VERSION 5.7 ;
  NOWIREEXTENSIONATPIN ON ;
  DIVIDERCHAR "/" ;
  BUSBITCHARS "[]" ;
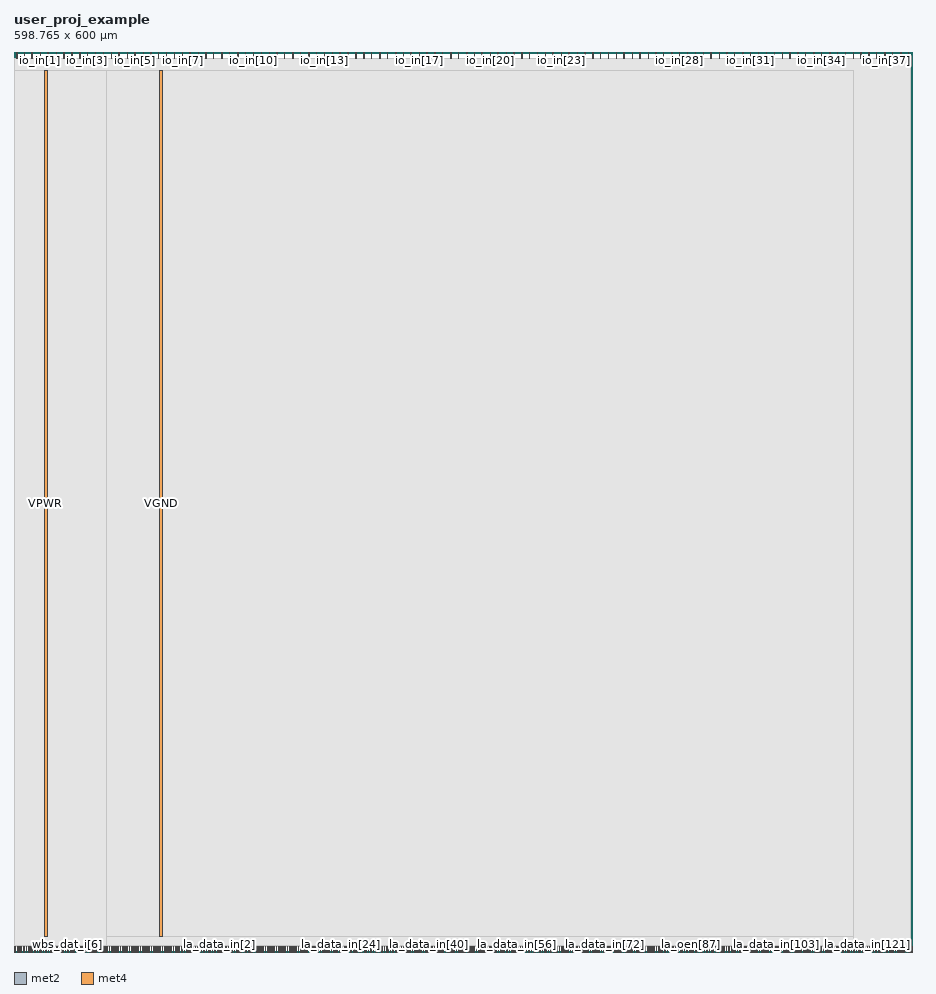
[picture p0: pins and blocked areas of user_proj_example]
MACRO user_proj_example
  CLASS BLOCK ;
  FOREIGN user_proj_example ;
  ORIGIN -0.005 0.000 ;
  SIZE 598.765 BY 600.000 ;
  PIN io_in[0]
    DIRECTION INPUT ;
    PORT
      LAYER met2 ;
        RECT 1.870 596.000 2.150 600.000 ;
    END
  END io_in[0]
  PIN io_in[10]
    DIRECTION INPUT ;
    PORT
      LAYER met2 ;
        RECT 159.650 596.000 159.930 600.000 ;
    END
  END io_in[10]
  PIN io_in[11]
    DIRECTION INPUT ;
    PORT
      LAYER met2 ;
        RECT 175.290 596.000 175.570 600.000 ;
    END
  END io_in[11]
  PIN io_in[12]
    DIRECTION INPUT ;
    PORT
      LAYER met2 ;
        RECT 190.930 596.000 191.210 600.000 ;
    END
  END io_in[12]
  PIN io_in[13]
    DIRECTION INPUT ;
    PORT
      LAYER met2 ;
        RECT 207.030 596.000 207.310 600.000 ;
    END
  END io_in[13]
  PIN io_in[14]
    DIRECTION INPUT ;
    PORT
      LAYER met2 ;
        RECT 222.670 596.000 222.950 600.000 ;
    END
  END io_in[14]
  PIN io_in[15]
    DIRECTION INPUT ;
    PORT
      LAYER met2 ;
        RECT 238.310 596.000 238.590 600.000 ;
    END
  END io_in[15]
  PIN io_in[16]
    DIRECTION INPUT ;
    PORT
      LAYER met2 ;
        RECT 254.410 596.000 254.690 600.000 ;
    END
  END io_in[16]
  PIN io_in[17]
    DIRECTION INPUT ;
    PORT
      LAYER met2 ;
        RECT 270.050 596.000 270.330 600.000 ;
    END
  END io_in[17]
  PIN io_in[18]
    DIRECTION INPUT ;
    PORT
      LAYER met2 ;
        RECT 285.690 596.000 285.970 600.000 ;
    END
  END io_in[18]
  PIN io_in[19]
    DIRECTION INPUT ;
    PORT
      LAYER met2 ;
        RECT 301.790 596.000 302.070 600.000 ;
    END
  END io_in[19]
  PIN io_in[1]
    DIRECTION INPUT ;
    PORT
      LAYER met2 ;
        RECT 17.510 596.000 17.790 600.000 ;
    END
  END io_in[1]
  PIN io_in[20]
    DIRECTION INPUT ;
    PORT
      LAYER met2 ;
        RECT 317.430 596.000 317.710 600.000 ;
    END
  END io_in[20]
  PIN io_in[21]
    DIRECTION INPUT ;
    PORT
      LAYER met2 ;
        RECT 333.070 596.000 333.350 600.000 ;
    END
  END io_in[21]
  PIN io_in[22]
    DIRECTION INPUT ;
    PORT
      LAYER met2 ;
        RECT 348.710 596.000 348.990 600.000 ;
    END
  END io_in[22]
  PIN io_in[23]
    DIRECTION INPUT ;
    PORT
      LAYER met2 ;
        RECT 364.810 596.000 365.090 600.000 ;
    END
  END io_in[23]
  PIN io_in[24]
    DIRECTION INPUT ;
    PORT
      LAYER met2 ;
        RECT 380.450 596.000 380.730 600.000 ;
    END
  END io_in[24]
  PIN io_in[25]
    DIRECTION INPUT ;
    PORT
      LAYER met2 ;
        RECT 396.090 596.000 396.370 600.000 ;
    END
  END io_in[25]
  PIN io_in[26]
    DIRECTION INPUT ;
    PORT
      LAYER met2 ;
        RECT 412.190 596.000 412.470 600.000 ;
    END
  END io_in[26]
  PIN io_in[27]
    DIRECTION INPUT ;
    PORT
      LAYER met2 ;
        RECT 427.830 596.000 428.110 600.000 ;
    END
  END io_in[27]
  PIN io_in[28]
    DIRECTION INPUT ;
    PORT
      LAYER met2 ;
        RECT 443.470 596.000 443.750 600.000 ;
    END
  END io_in[28]
  PIN io_in[29]
    DIRECTION INPUT ;
    PORT
      LAYER met2 ;
        RECT 459.570 596.000 459.850 600.000 ;
    END
  END io_in[29]
  PIN io_in[2]
    DIRECTION INPUT ;
    PORT
      LAYER met2 ;
        RECT 33.150 596.000 33.430 600.000 ;
    END
  END io_in[2]
  PIN io_in[30]
    DIRECTION INPUT ;
    PORT
      LAYER met2 ;
        RECT 475.210 596.000 475.490 600.000 ;
    END
  END io_in[30]
  PIN io_in[31]
    DIRECTION INPUT ;
    PORT
      LAYER met2 ;
        RECT 490.850 596.000 491.130 600.000 ;
    END
  END io_in[31]
  PIN io_in[32]
    DIRECTION INPUT ;
    PORT
      LAYER met2 ;
        RECT 506.950 596.000 507.230 600.000 ;
    END
  END io_in[32]
  PIN io_in[33]
    DIRECTION INPUT ;
    PORT
      LAYER met2 ;
        RECT 522.590 596.000 522.870 600.000 ;
    END
  END io_in[33]
  PIN io_in[34]
    DIRECTION INPUT ;
    PORT
      LAYER met2 ;
        RECT 538.230 596.000 538.510 600.000 ;
    END
  END io_in[34]
  PIN io_in[35]
    DIRECTION INPUT ;
    PORT
      LAYER met2 ;
        RECT 554.330 596.000 554.610 600.000 ;
    END
  END io_in[35]
  PIN io_in[36]
    DIRECTION INPUT ;
    PORT
      LAYER met2 ;
        RECT 569.970 596.000 570.250 600.000 ;
    END
  END io_in[36]
  PIN io_in[37]
    DIRECTION INPUT ;
    PORT
      LAYER met2 ;
        RECT 585.610 596.000 585.890 600.000 ;
    END
  END io_in[37]
  PIN io_in[3]
    DIRECTION INPUT ;
    PORT
      LAYER met2 ;
        RECT 48.790 596.000 49.070 600.000 ;
    END
  END io_in[3]
  PIN io_in[4]
    DIRECTION INPUT ;
    PORT
      LAYER met2 ;
        RECT 64.890 596.000 65.170 600.000 ;
    END
  END io_in[4]
  PIN io_in[5]
    DIRECTION INPUT ;
    PORT
      LAYER met2 ;
        RECT 80.530 596.000 80.810 600.000 ;
    END
  END io_in[5]
  PIN io_in[6]
    DIRECTION INPUT ;
    PORT
      LAYER met2 ;
        RECT 96.170 596.000 96.450 600.000 ;
    END
  END io_in[6]
  PIN io_in[7]
    DIRECTION INPUT ;
    PORT
      LAYER met2 ;
        RECT 112.270 596.000 112.550 600.000 ;
    END
  END io_in[7]
  PIN io_in[8]
    DIRECTION INPUT ;
    PORT
      LAYER met2 ;
        RECT 127.910 596.000 128.190 600.000 ;
    END
  END io_in[8]
  PIN io_in[9]
    DIRECTION INPUT ;
    PORT
      LAYER met2 ;
        RECT 143.550 596.000 143.830 600.000 ;
    END
  END io_in[9]
  PIN io_oeb[0]
    DIRECTION OUTPUT TRISTATE ;
    PORT
      LAYER met2 ;
        RECT 6.930 596.000 7.210 600.000 ;
    END
  END io_oeb[0]
  PIN io_oeb[10]
    DIRECTION OUTPUT TRISTATE ;
    PORT
      LAYER met2 ;
        RECT 164.710 596.000 164.990 600.000 ;
    END
  END io_oeb[10]
  PIN io_oeb[11]
    DIRECTION OUTPUT TRISTATE ;
    PORT
      LAYER met2 ;
        RECT 180.350 596.000 180.630 600.000 ;
    END
  END io_oeb[11]
  PIN io_oeb[12]
    DIRECTION OUTPUT TRISTATE ;
    PORT
      LAYER met2 ;
        RECT 196.450 596.000 196.730 600.000 ;
    END
  END io_oeb[12]
  PIN io_oeb[13]
    DIRECTION OUTPUT TRISTATE ;
    PORT
      LAYER met2 ;
        RECT 212.090 596.000 212.370 600.000 ;
    END
  END io_oeb[13]
  PIN io_oeb[14]
    DIRECTION OUTPUT TRISTATE ;
    PORT
      LAYER met2 ;
        RECT 227.730 596.000 228.010 600.000 ;
    END
  END io_oeb[14]
  PIN io_oeb[15]
    DIRECTION OUTPUT TRISTATE ;
    PORT
      LAYER met2 ;
        RECT 243.830 596.000 244.110 600.000 ;
    END
  END io_oeb[15]
  PIN io_oeb[16]
    DIRECTION OUTPUT TRISTATE ;
    PORT
      LAYER met2 ;
        RECT 259.470 596.000 259.750 600.000 ;
    END
  END io_oeb[16]
  PIN io_oeb[17]
    DIRECTION OUTPUT TRISTATE ;
    PORT
      LAYER met2 ;
        RECT 275.110 596.000 275.390 600.000 ;
    END
  END io_oeb[17]
  PIN io_oeb[18]
    DIRECTION OUTPUT TRISTATE ;
    PORT
      LAYER met2 ;
        RECT 291.210 596.000 291.490 600.000 ;
    END
  END io_oeb[18]
  PIN io_oeb[19]
    DIRECTION OUTPUT TRISTATE ;
    PORT
      LAYER met2 ;
        RECT 306.850 596.000 307.130 600.000 ;
    END
  END io_oeb[19]
  PIN io_oeb[1]
    DIRECTION OUTPUT TRISTATE ;
    PORT
      LAYER met2 ;
        RECT 22.570 596.000 22.850 600.000 ;
    END
  END io_oeb[1]
  PIN io_oeb[20]
    DIRECTION OUTPUT TRISTATE ;
    PORT
      LAYER met2 ;
        RECT 322.490 596.000 322.770 600.000 ;
    END
  END io_oeb[20]
  PIN io_oeb[21]
    DIRECTION OUTPUT TRISTATE ;
    PORT
      LAYER met2 ;
        RECT 338.590 596.000 338.870 600.000 ;
    END
  END io_oeb[21]
  PIN io_oeb[22]
    DIRECTION OUTPUT TRISTATE ;
    PORT
      LAYER met2 ;
        RECT 354.230 596.000 354.510 600.000 ;
    END
  END io_oeb[22]
  PIN io_oeb[23]
    DIRECTION OUTPUT TRISTATE ;
    PORT
      LAYER met2 ;
        RECT 369.870 596.000 370.150 600.000 ;
    END
  END io_oeb[23]
  PIN io_oeb[24]
    DIRECTION OUTPUT TRISTATE ;
    PORT
      LAYER met2 ;
        RECT 385.970 596.000 386.250 600.000 ;
    END
  END io_oeb[24]
  PIN io_oeb[25]
    DIRECTION OUTPUT TRISTATE ;
    PORT
      LAYER met2 ;
        RECT 401.610 596.000 401.890 600.000 ;
    END
  END io_oeb[25]
  PIN io_oeb[26]
    DIRECTION OUTPUT TRISTATE ;
    PORT
      LAYER met2 ;
        RECT 417.250 596.000 417.530 600.000 ;
    END
  END io_oeb[26]
  PIN io_oeb[27]
    DIRECTION OUTPUT TRISTATE ;
    PORT
      LAYER met2 ;
        RECT 432.890 596.000 433.170 600.000 ;
    END
  END io_oeb[27]
  PIN io_oeb[28]
    DIRECTION OUTPUT TRISTATE ;
    PORT
      LAYER met2 ;
        RECT 448.990 596.000 449.270 600.000 ;
    END
  END io_oeb[28]
  PIN io_oeb[29]
    DIRECTION OUTPUT TRISTATE ;
    PORT
      LAYER met2 ;
        RECT 464.630 596.000 464.910 600.000 ;
    END
  END io_oeb[29]
  PIN io_oeb[2]
    DIRECTION OUTPUT TRISTATE ;
    PORT
      LAYER met2 ;
        RECT 38.670 596.000 38.950 600.000 ;
    END
  END io_oeb[2]
  PIN io_oeb[30]
    DIRECTION OUTPUT TRISTATE ;
    PORT
      LAYER met2 ;
        RECT 480.270 596.000 480.550 600.000 ;
    END
  END io_oeb[30]
  PIN io_oeb[31]
    DIRECTION OUTPUT TRISTATE ;
    PORT
      LAYER met2 ;
        RECT 496.370 596.000 496.650 600.000 ;
    END
  END io_oeb[31]
  PIN io_oeb[32]
    DIRECTION OUTPUT TRISTATE ;
    PORT
      LAYER met2 ;
        RECT 512.010 596.000 512.290 600.000 ;
    END
  END io_oeb[32]
  PIN io_oeb[33]
    DIRECTION OUTPUT TRISTATE ;
    PORT
      LAYER met2 ;
        RECT 527.650 596.000 527.930 600.000 ;
    END
  END io_oeb[33]
  PIN io_oeb[34]
    DIRECTION OUTPUT TRISTATE ;
    PORT
      LAYER met2 ;
        RECT 543.750 596.000 544.030 600.000 ;
    END
  END io_oeb[34]
  PIN io_oeb[35]
    DIRECTION OUTPUT TRISTATE ;
    PORT
      LAYER met2 ;
        RECT 559.390 596.000 559.670 600.000 ;
    END
  END io_oeb[35]
  PIN io_oeb[36]
    DIRECTION OUTPUT TRISTATE ;
    PORT
      LAYER met2 ;
        RECT 575.030 596.000 575.310 600.000 ;
    END
  END io_oeb[36]
  PIN io_oeb[37]
    DIRECTION OUTPUT TRISTATE ;
    PORT
      LAYER met2 ;
        RECT 591.130 596.000 591.410 600.000 ;
    END
  END io_oeb[37]
  PIN io_oeb[3]
    DIRECTION OUTPUT TRISTATE ;
    PORT
      LAYER met2 ;
        RECT 54.310 596.000 54.590 600.000 ;
    END
  END io_oeb[3]
  PIN io_oeb[4]
    DIRECTION OUTPUT TRISTATE ;
    PORT
      LAYER met2 ;
        RECT 69.950 596.000 70.230 600.000 ;
    END
  END io_oeb[4]
  PIN io_oeb[5]
    DIRECTION OUTPUT TRISTATE ;
    PORT
      LAYER met2 ;
        RECT 86.050 596.000 86.330 600.000 ;
    END
  END io_oeb[5]
  PIN io_oeb[6]
    DIRECTION OUTPUT TRISTATE ;
    PORT
      LAYER met2 ;
        RECT 101.690 596.000 101.970 600.000 ;
    END
  END io_oeb[6]
  PIN io_oeb[7]
    DIRECTION OUTPUT TRISTATE ;
    PORT
      LAYER met2 ;
        RECT 117.330 596.000 117.610 600.000 ;
    END
  END io_oeb[7]
  PIN io_oeb[8]
    DIRECTION OUTPUT TRISTATE ;
    PORT
      LAYER met2 ;
        RECT 132.970 596.000 133.250 600.000 ;
    END
  END io_oeb[8]
  PIN io_oeb[9]
    DIRECTION OUTPUT TRISTATE ;
    PORT
      LAYER met2 ;
        RECT 149.070 596.000 149.350 600.000 ;
    END
  END io_oeb[9]
  PIN io_out[0]
    DIRECTION OUTPUT TRISTATE ;
    PORT
      LAYER met2 ;
        RECT 11.990 596.000 12.270 600.000 ;
    END
  END io_out[0]
  PIN io_out[10]
    DIRECTION OUTPUT TRISTATE ;
    PORT
      LAYER met2 ;
        RECT 170.230 596.000 170.510 600.000 ;
    END
  END io_out[10]
  PIN io_out[11]
    DIRECTION OUTPUT TRISTATE ;
    PORT
      LAYER met2 ;
        RECT 185.870 596.000 186.150 600.000 ;
    END
  END io_out[11]
  PIN io_out[12]
    DIRECTION OUTPUT TRISTATE ;
    PORT
      LAYER met2 ;
        RECT 201.510 596.000 201.790 600.000 ;
    END
  END io_out[12]
  PIN io_out[13]
    DIRECTION OUTPUT TRISTATE ;
    PORT
      LAYER met2 ;
        RECT 217.150 596.000 217.430 600.000 ;
    END
  END io_out[13]
  PIN io_out[14]
    DIRECTION OUTPUT TRISTATE ;
    PORT
      LAYER met2 ;
        RECT 233.250 596.000 233.530 600.000 ;
    END
  END io_out[14]
  PIN io_out[15]
    DIRECTION OUTPUT TRISTATE ;
    PORT
      LAYER met2 ;
        RECT 248.890 596.000 249.170 600.000 ;
    END
  END io_out[15]
  PIN io_out[16]
    DIRECTION OUTPUT TRISTATE ;
    PORT
      LAYER met2 ;
        RECT 264.530 596.000 264.810 600.000 ;
    END
  END io_out[16]
  PIN io_out[17]
    DIRECTION OUTPUT TRISTATE ;
    PORT
      LAYER met2 ;
        RECT 280.630 596.000 280.910 600.000 ;
    END
  END io_out[17]
  PIN io_out[18]
    DIRECTION OUTPUT TRISTATE ;
    PORT
      LAYER met2 ;
        RECT 296.270 596.000 296.550 600.000 ;
    END
  END io_out[18]
  PIN io_out[19]
    DIRECTION OUTPUT TRISTATE ;
    PORT
      LAYER met2 ;
        RECT 311.910 596.000 312.190 600.000 ;
    END
  END io_out[19]
  PIN io_out[1]
    DIRECTION OUTPUT TRISTATE ;
    PORT
      LAYER met2 ;
        RECT 28.090 596.000 28.370 600.000 ;
    END
  END io_out[1]
  PIN io_out[20]
    DIRECTION OUTPUT TRISTATE ;
    PORT
      LAYER met2 ;
        RECT 328.010 596.000 328.290 600.000 ;
    END
  END io_out[20]
  PIN io_out[21]
    DIRECTION OUTPUT TRISTATE ;
    PORT
      LAYER met2 ;
        RECT 343.650 596.000 343.930 600.000 ;
    END
  END io_out[21]
  PIN io_out[22]
    DIRECTION OUTPUT TRISTATE ;
    PORT
      LAYER met2 ;
        RECT 359.290 596.000 359.570 600.000 ;
    END
  END io_out[22]
  PIN io_out[23]
    DIRECTION OUTPUT TRISTATE ;
    PORT
      LAYER met2 ;
        RECT 375.390 596.000 375.670 600.000 ;
    END
  END io_out[23]
  PIN io_out[24]
    DIRECTION OUTPUT TRISTATE ;
    PORT
      LAYER met2 ;
        RECT 391.030 596.000 391.310 600.000 ;
    END
  END io_out[24]
  PIN io_out[25]
    DIRECTION OUTPUT TRISTATE ;
    PORT
      LAYER met2 ;
        RECT 406.670 596.000 406.950 600.000 ;
    END
  END io_out[25]
  PIN io_out[26]
    DIRECTION OUTPUT TRISTATE ;
    PORT
      LAYER met2 ;
        RECT 422.770 596.000 423.050 600.000 ;
    END
  END io_out[26]
  PIN io_out[27]
    DIRECTION OUTPUT TRISTATE ;
    PORT
      LAYER met2 ;
        RECT 438.410 596.000 438.690 600.000 ;
    END
  END io_out[27]
  PIN io_out[28]
    DIRECTION OUTPUT TRISTATE ;
    PORT
      LAYER met2 ;
        RECT 454.050 596.000 454.330 600.000 ;
    END
  END io_out[28]
  PIN io_out[29]
    DIRECTION OUTPUT TRISTATE ;
    PORT
      LAYER met2 ;
        RECT 470.150 596.000 470.430 600.000 ;
    END
  END io_out[29]
  PIN io_out[2]
    DIRECTION OUTPUT TRISTATE ;
    PORT
      LAYER met2 ;
        RECT 43.730 596.000 44.010 600.000 ;
    END
  END io_out[2]
  PIN io_out[30]
    DIRECTION OUTPUT TRISTATE ;
    PORT
      LAYER met2 ;
        RECT 485.790 596.000 486.070 600.000 ;
    END
  END io_out[30]
  PIN io_out[31]
    DIRECTION OUTPUT TRISTATE ;
    PORT
      LAYER met2 ;
        RECT 501.430 596.000 501.710 600.000 ;
    END
  END io_out[31]
  PIN io_out[32]
    DIRECTION OUTPUT TRISTATE ;
    PORT
      LAYER met2 ;
        RECT 517.070 596.000 517.350 600.000 ;
    END
  END io_out[32]
  PIN io_out[33]
    DIRECTION OUTPUT TRISTATE ;
    PORT
      LAYER met2 ;
        RECT 533.170 596.000 533.450 600.000 ;
    END
  END io_out[33]
  PIN io_out[34]
    DIRECTION OUTPUT TRISTATE ;
    PORT
      LAYER met2 ;
        RECT 548.810 596.000 549.090 600.000 ;
    END
  END io_out[34]
  PIN io_out[35]
    DIRECTION OUTPUT TRISTATE ;
    PORT
      LAYER met2 ;
        RECT 564.450 596.000 564.730 600.000 ;
    END
  END io_out[35]
  PIN io_out[36]
    DIRECTION OUTPUT TRISTATE ;
    PORT
      LAYER met2 ;
        RECT 580.550 596.000 580.830 600.000 ;
    END
  END io_out[36]
  PIN io_out[37]
    DIRECTION OUTPUT TRISTATE ;
    PORT
      LAYER met2 ;
        RECT 596.190 596.000 596.470 600.000 ;
    END
  END io_out[37]
  PIN io_out[3]
    DIRECTION OUTPUT TRISTATE ;
    PORT
      LAYER met2 ;
        RECT 59.370 596.000 59.650 600.000 ;
    END
  END io_out[3]
  PIN io_out[4]
    DIRECTION OUTPUT TRISTATE ;
    PORT
      LAYER met2 ;
        RECT 75.470 596.000 75.750 600.000 ;
    END
  END io_out[4]
  PIN io_out[5]
    DIRECTION OUTPUT TRISTATE ;
    PORT
      LAYER met2 ;
        RECT 91.110 596.000 91.390 600.000 ;
    END
  END io_out[5]
  PIN io_out[6]
    DIRECTION OUTPUT TRISTATE ;
    PORT
      LAYER met2 ;
        RECT 106.750 596.000 107.030 600.000 ;
    END
  END io_out[6]
  PIN io_out[7]
    DIRECTION OUTPUT TRISTATE ;
    PORT
      LAYER met2 ;
        RECT 122.850 596.000 123.130 600.000 ;
    END
  END io_out[7]
  PIN io_out[8]
    DIRECTION OUTPUT TRISTATE ;
    PORT
      LAYER met2 ;
        RECT 138.490 596.000 138.770 600.000 ;
    END
  END io_out[8]
  PIN io_out[9]
    DIRECTION OUTPUT TRISTATE ;
    PORT
      LAYER met2 ;
        RECT 154.130 596.000 154.410 600.000 ;
    END
  END io_out[9]
  PIN la_data_in[0]
    DIRECTION INPUT ;
    PORT
      LAYER met2 ;
        RECT 129.750 0.000 130.030 4.000 ;
    END
  END la_data_in[0]
  PIN la_data_in[100]
    DIRECTION INPUT ;
    PORT
      LAYER met2 ;
        RECT 496.830 0.000 497.110 4.000 ;
    END
  END la_data_in[100]
  PIN la_data_in[101]
    DIRECTION INPUT ;
    PORT
      LAYER met2 ;
        RECT 500.510 0.000 500.790 4.000 ;
    END
  END la_data_in[101]
  PIN la_data_in[102]
    DIRECTION INPUT ;
    PORT
      LAYER met2 ;
        RECT 504.190 0.000 504.470 4.000 ;
    END
  END la_data_in[102]
  PIN la_data_in[103]
    DIRECTION INPUT ;
    PORT
      LAYER met2 ;
        RECT 507.870 0.000 508.150 4.000 ;
    END
  END la_data_in[103]
  PIN la_data_in[104]
    DIRECTION INPUT ;
    PORT
      LAYER met2 ;
        RECT 511.550 0.000 511.830 4.000 ;
    END
  END la_data_in[104]
  PIN la_data_in[105]
    DIRECTION INPUT ;
    PORT
      LAYER met2 ;
        RECT 515.230 0.000 515.510 4.000 ;
    END
  END la_data_in[105]
  PIN la_data_in[106]
    DIRECTION INPUT ;
    PORT
      LAYER met2 ;
        RECT 518.910 0.000 519.190 4.000 ;
    END
  END la_data_in[106]
  PIN la_data_in[107]
    DIRECTION INPUT ;
    PORT
      LAYER met2 ;
        RECT 522.590 0.000 522.870 4.000 ;
    END
  END la_data_in[107]
  PIN la_data_in[108]
    DIRECTION INPUT ;
    PORT
      LAYER met2 ;
        RECT 526.270 0.000 526.550 4.000 ;
    END
  END la_data_in[108]
  PIN la_data_in[109]
    DIRECTION INPUT ;
    PORT
      LAYER met2 ;
        RECT 529.950 0.000 530.230 4.000 ;
    END
  END la_data_in[109]
  PIN la_data_in[10]
    DIRECTION INPUT ;
    PORT
      LAYER met2 ;
        RECT 166.090 0.000 166.370 4.000 ;
    END
  END la_data_in[10]
  PIN la_data_in[110]
    DIRECTION INPUT ;
    PORT
      LAYER met2 ;
        RECT 533.630 0.000 533.910 4.000 ;
    END
  END la_data_in[110]
  PIN la_data_in[111]
    DIRECTION INPUT ;
    PORT
      LAYER met2 ;
        RECT 537.310 0.000 537.590 4.000 ;
    END
  END la_data_in[111]
  PIN la_data_in[112]
    DIRECTION INPUT ;
    PORT
      LAYER met2 ;
        RECT 540.990 0.000 541.270 4.000 ;
    END
  END la_data_in[112]
  PIN la_data_in[113]
    DIRECTION INPUT ;
    PORT
      LAYER met2 ;
        RECT 544.670 0.000 544.950 4.000 ;
    END
  END la_data_in[113]
  PIN la_data_in[114]
    DIRECTION INPUT ;
    PORT
      LAYER met2 ;
        RECT 548.350 0.000 548.630 4.000 ;
    END
  END la_data_in[114]
  PIN la_data_in[115]
    DIRECTION INPUT ;
    PORT
      LAYER met2 ;
        RECT 552.030 0.000 552.310 4.000 ;
    END
  END la_data_in[115]
  PIN la_data_in[116]
    DIRECTION INPUT ;
    PORT
      LAYER met2 ;
        RECT 555.710 0.000 555.990 4.000 ;
    END
  END la_data_in[116]
  PIN la_data_in[117]
    DIRECTION INPUT ;
    PORT
      LAYER met2 ;
        RECT 559.390 0.000 559.670 4.000 ;
    END
  END la_data_in[117]
  PIN la_data_in[118]
    DIRECTION INPUT ;
    PORT
      LAYER met2 ;
        RECT 563.070 0.000 563.350 4.000 ;
    END
  END la_data_in[118]
  PIN la_data_in[119]
    DIRECTION INPUT ;
    PORT
      LAYER met2 ;
        RECT 566.750 0.000 567.030 4.000 ;
    END
  END la_data_in[119]
  PIN la_data_in[11]
    DIRECTION INPUT ;
    PORT
      LAYER met2 ;
        RECT 169.770 0.000 170.050 4.000 ;
    END
  END la_data_in[11]
  PIN la_data_in[120]
    DIRECTION INPUT ;
    PORT
      LAYER met2 ;
        RECT 570.430 0.000 570.710 4.000 ;
    END
  END la_data_in[120]
  PIN la_data_in[121]
    DIRECTION INPUT ;
    PORT
      LAYER met2 ;
        RECT 574.110 0.000 574.390 4.000 ;
    END
  END la_data_in[121]
  PIN la_data_in[122]
    DIRECTION INPUT ;
    PORT
      LAYER met2 ;
        RECT 577.790 0.000 578.070 4.000 ;
    END
  END la_data_in[122]
  PIN la_data_in[123]
    DIRECTION INPUT ;
    PORT
      LAYER met2 ;
        RECT 581.470 0.000 581.750 4.000 ;
    END
  END la_data_in[123]
  PIN la_data_in[124]
    DIRECTION INPUT ;
    PORT
      LAYER met2 ;
        RECT 585.150 0.000 585.430 4.000 ;
    END
  END la_data_in[124]
  PIN la_data_in[125]
    DIRECTION INPUT ;
    PORT
      LAYER met2 ;
        RECT 588.830 0.000 589.110 4.000 ;
    END
  END la_data_in[125]
  PIN la_data_in[126]
    DIRECTION INPUT ;
    PORT
      LAYER met2 ;
        RECT 592.510 0.000 592.790 4.000 ;
    END
  END la_data_in[126]
  PIN la_data_in[127]
    DIRECTION INPUT ;
    PORT
      LAYER met2 ;
        RECT 596.190 0.000 596.470 4.000 ;
    END
  END la_data_in[127]
  PIN la_data_in[12]
    DIRECTION INPUT ;
    PORT
      LAYER met2 ;
        RECT 173.450 0.000 173.730 4.000 ;
    END
  END la_data_in[12]
  PIN la_data_in[13]
    DIRECTION INPUT ;
    PORT
      LAYER met2 ;
        RECT 177.130 0.000 177.410 4.000 ;
    END
  END la_data_in[13]
  PIN la_data_in[14]
    DIRECTION INPUT ;
    PORT
      LAYER met2 ;
        RECT 180.810 0.000 181.090 4.000 ;
    END
  END la_data_in[14]
  PIN la_data_in[15]
    DIRECTION INPUT ;
    PORT
      LAYER met2 ;
        RECT 184.490 0.000 184.770 4.000 ;
    END
  END la_data_in[15]
  PIN la_data_in[16]
    DIRECTION INPUT ;
    PORT
      LAYER met2 ;
        RECT 188.170 0.000 188.450 4.000 ;
    END
  END la_data_in[16]
  PIN la_data_in[17]
    DIRECTION INPUT ;
    PORT
      LAYER met2 ;
        RECT 191.850 0.000 192.130 4.000 ;
    END
  END la_data_in[17]
  PIN la_data_in[18]
    DIRECTION INPUT ;
    PORT
      LAYER met2 ;
        RECT 195.530 0.000 195.810 4.000 ;
    END
  END la_data_in[18]
  PIN la_data_in[19]
    DIRECTION INPUT ;
    PORT
      LAYER met2 ;
        RECT 199.210 0.000 199.490 4.000 ;
    END
  END la_data_in[19]
  PIN la_data_in[1]
    DIRECTION INPUT ;
    PORT
      LAYER met2 ;
        RECT 133.430 0.000 133.710 4.000 ;
    END
  END la_data_in[1]
  PIN la_data_in[20]
    DIRECTION INPUT ;
    PORT
      LAYER met2 ;
        RECT 202.890 0.000 203.170 4.000 ;
    END
  END la_data_in[20]
  PIN la_data_in[21]
    DIRECTION INPUT ;
    PORT
      LAYER met2 ;
        RECT 206.570 0.000 206.850 4.000 ;
    END
  END la_data_in[21]
  PIN la_data_in[22]
    DIRECTION INPUT ;
    PORT
      LAYER met2 ;
        RECT 210.250 0.000 210.530 4.000 ;
    END
  END la_data_in[22]
  PIN la_data_in[23]
    DIRECTION INPUT ;
    PORT
      LAYER met2 ;
        RECT 213.930 0.000 214.210 4.000 ;
    END
  END la_data_in[23]
  PIN la_data_in[24]
    DIRECTION INPUT ;
    PORT
      LAYER met2 ;
        RECT 217.610 0.000 217.890 4.000 ;
    END
  END la_data_in[24]
  PIN la_data_in[25]
    DIRECTION INPUT ;
    PORT
      LAYER met2 ;
        RECT 221.290 0.000 221.570 4.000 ;
    END
  END la_data_in[25]
  PIN la_data_in[26]
    DIRECTION INPUT ;
    PORT
      LAYER met2 ;
        RECT 224.970 0.000 225.250 4.000 ;
    END
  END la_data_in[26]
  PIN la_data_in[27]
    DIRECTION INPUT ;
    PORT
      LAYER met2 ;
        RECT 228.650 0.000 228.930 4.000 ;
    END
  END la_data_in[27]
  PIN la_data_in[28]
    DIRECTION INPUT ;
    PORT
      LAYER met2 ;
        RECT 232.330 0.000 232.610 4.000 ;
    END
  END la_data_in[28]
  PIN la_data_in[29]
    DIRECTION INPUT ;
    PORT
      LAYER met2 ;
        RECT 236.010 0.000 236.290 4.000 ;
    END
  END la_data_in[29]
  PIN la_data_in[2]
    DIRECTION INPUT ;
    PORT
      LAYER met2 ;
        RECT 137.110 0.000 137.390 4.000 ;
    END
  END la_data_in[2]
  PIN la_data_in[30]
    DIRECTION INPUT ;
    PORT
      LAYER met2 ;
        RECT 239.690 0.000 239.970 4.000 ;
    END
  END la_data_in[30]
  PIN la_data_in[31]
    DIRECTION INPUT ;
    PORT
      LAYER met2 ;
        RECT 243.370 0.000 243.650 4.000 ;
    END
  END la_data_in[31]
  PIN la_data_in[32]
    DIRECTION INPUT ;
    PORT
      LAYER met2 ;
        RECT 247.050 0.000 247.330 4.000 ;
    END
  END la_data_in[32]
  PIN la_data_in[33]
    DIRECTION INPUT ;
    PORT
      LAYER met2 ;
        RECT 250.730 0.000 251.010 4.000 ;
    END
  END la_data_in[33]
  PIN la_data_in[34]
    DIRECTION INPUT ;
    PORT
      LAYER met2 ;
        RECT 254.410 0.000 254.690 4.000 ;
    END
  END la_data_in[34]
  PIN la_data_in[35]
    DIRECTION INPUT ;
    PORT
      LAYER met2 ;
        RECT 258.090 0.000 258.370 4.000 ;
    END
  END la_data_in[35]
  PIN la_data_in[36]
    DIRECTION INPUT ;
    PORT
      LAYER met2 ;
        RECT 261.770 0.000 262.050 4.000 ;
    END
  END la_data_in[36]
  PIN la_data_in[37]
    DIRECTION INPUT ;
    PORT
      LAYER met2 ;
        RECT 265.450 0.000 265.730 4.000 ;
    END
  END la_data_in[37]
  PIN la_data_in[38]
    DIRECTION INPUT ;
    PORT
      LAYER met2 ;
        RECT 269.130 0.000 269.410 4.000 ;
    END
  END la_data_in[38]
  PIN la_data_in[39]
    DIRECTION INPUT ;
    PORT
      LAYER met2 ;
        RECT 272.810 0.000 273.090 4.000 ;
    END
  END la_data_in[39]
  PIN la_data_in[3]
    DIRECTION INPUT ;
    PORT
      LAYER met2 ;
        RECT 140.790 0.000 141.070 4.000 ;
    END
  END la_data_in[3]
  PIN la_data_in[40]
    DIRECTION INPUT ;
    PORT
      LAYER met2 ;
        RECT 276.490 0.000 276.770 4.000 ;
    END
  END la_data_in[40]
  PIN la_data_in[41]
    DIRECTION INPUT ;
    PORT
      LAYER met2 ;
        RECT 280.170 0.000 280.450 4.000 ;
    END
  END la_data_in[41]
  PIN la_data_in[42]
    DIRECTION INPUT ;
    PORT
      LAYER met2 ;
        RECT 283.850 0.000 284.130 4.000 ;
    END
  END la_data_in[42]
  PIN la_data_in[43]
    DIRECTION INPUT ;
    PORT
      LAYER met2 ;
        RECT 287.530 0.000 287.810 4.000 ;
    END
  END la_data_in[43]
  PIN la_data_in[44]
    DIRECTION INPUT ;
    PORT
      LAYER met2 ;
        RECT 291.210 0.000 291.490 4.000 ;
    END
  END la_data_in[44]
  PIN la_data_in[45]
    DIRECTION INPUT ;
    PORT
      LAYER met2 ;
        RECT 294.890 0.000 295.170 4.000 ;
    END
  END la_data_in[45]
  PIN la_data_in[46]
    DIRECTION INPUT ;
    PORT
      LAYER met2 ;
        RECT 298.570 0.000 298.850 4.000 ;
    END
  END la_data_in[46]
  PIN la_data_in[47]
    DIRECTION INPUT ;
    PORT
      LAYER met2 ;
        RECT 302.250 0.000 302.530 4.000 ;
    END
  END la_data_in[47]
  PIN la_data_in[48]
    DIRECTION INPUT ;
    PORT
      LAYER met2 ;
        RECT 305.930 0.000 306.210 4.000 ;
    END
  END la_data_in[48]
  PIN la_data_in[49]
    DIRECTION INPUT ;
    PORT
      LAYER met2 ;
        RECT 309.610 0.000 309.890 4.000 ;
    END
  END la_data_in[49]
  PIN la_data_in[4]
    DIRECTION INPUT ;
    PORT
      LAYER met2 ;
        RECT 144.470 0.000 144.750 4.000 ;
    END
  END la_data_in[4]
  PIN la_data_in[50]
    DIRECTION INPUT ;
    PORT
      LAYER met2 ;
        RECT 313.290 0.000 313.570 4.000 ;
    END
  END la_data_in[50]
  PIN la_data_in[51]
    DIRECTION INPUT ;
    PORT
      LAYER met2 ;
        RECT 316.970 0.000 317.250 4.000 ;
    END
  END la_data_in[51]
  PIN la_data_in[52]
    DIRECTION INPUT ;
    PORT
      LAYER met2 ;
        RECT 320.650 0.000 320.930 4.000 ;
    END
  END la_data_in[52]
  PIN la_data_in[53]
    DIRECTION INPUT ;
    PORT
      LAYER met2 ;
        RECT 324.330 0.000 324.610 4.000 ;
    END
  END la_data_in[53]
  PIN la_data_in[54]
    DIRECTION INPUT ;
    PORT
      LAYER met2 ;
        RECT 328.010 0.000 328.290 4.000 ;
    END
  END la_data_in[54]
  PIN la_data_in[55]
    DIRECTION INPUT ;
    PORT
      LAYER met2 ;
        RECT 331.690 0.000 331.970 4.000 ;
    END
  END la_data_in[55]
  PIN la_data_in[56]
    DIRECTION INPUT ;
    PORT
      LAYER met2 ;
        RECT 335.370 0.000 335.650 4.000 ;
    END
  END la_data_in[56]
  PIN la_data_in[57]
    DIRECTION INPUT ;
    PORT
      LAYER met2 ;
        RECT 339.050 0.000 339.330 4.000 ;
    END
  END la_data_in[57]
  PIN la_data_in[58]
    DIRECTION INPUT ;
    PORT
      LAYER met2 ;
        RECT 342.730 0.000 343.010 4.000 ;
    END
  END la_data_in[58]
  PIN la_data_in[59]
    DIRECTION INPUT ;
    PORT
      LAYER met2 ;
        RECT 346.410 0.000 346.690 4.000 ;
    END
  END la_data_in[59]
  PIN la_data_in[5]
    DIRECTION INPUT ;
    PORT
      LAYER met2 ;
        RECT 148.150 0.000 148.430 4.000 ;
    END
  END la_data_in[5]
  PIN la_data_in[60]
    DIRECTION INPUT ;
    PORT
      LAYER met2 ;
        RECT 350.090 0.000 350.370 4.000 ;
    END
  END la_data_in[60]
  PIN la_data_in[61]
    DIRECTION INPUT ;
    PORT
      LAYER met2 ;
        RECT 353.770 0.000 354.050 4.000 ;
    END
  END la_data_in[61]
  PIN la_data_in[62]
    DIRECTION INPUT ;
    PORT
      LAYER met2 ;
        RECT 357.450 0.000 357.730 4.000 ;
    END
  END la_data_in[62]
  PIN la_data_in[63]
    DIRECTION INPUT ;
    PORT
      LAYER met2 ;
        RECT 361.130 0.000 361.410 4.000 ;
    END
  END la_data_in[63]
  PIN la_data_in[64]
    DIRECTION INPUT ;
    PORT
      LAYER met2 ;
        RECT 364.810 0.000 365.090 4.000 ;
    END
  END la_data_in[64]
  PIN la_data_in[65]
    DIRECTION INPUT ;
    PORT
      LAYER met2 ;
        RECT 368.490 0.000 368.770 4.000 ;
    END
  END la_data_in[65]
  PIN la_data_in[66]
    DIRECTION INPUT ;
    PORT
      LAYER met2 ;
        RECT 372.170 0.000 372.450 4.000 ;
    END
  END la_data_in[66]
  PIN la_data_in[67]
    DIRECTION INPUT ;
    PORT
      LAYER met2 ;
        RECT 375.390 0.000 375.670 4.000 ;
    END
  END la_data_in[67]
  PIN la_data_in[68]
    DIRECTION INPUT ;
    PORT
      LAYER met2 ;
        RECT 379.070 0.000 379.350 4.000 ;
    END
  END la_data_in[68]
  PIN la_data_in[69]
    DIRECTION INPUT ;
    PORT
      LAYER met2 ;
        RECT 382.750 0.000 383.030 4.000 ;
    END
  END la_data_in[69]
  PIN la_data_in[6]
    DIRECTION INPUT ;
    PORT
      LAYER met2 ;
        RECT 151.370 0.000 151.650 4.000 ;
    END
  END la_data_in[6]
  PIN la_data_in[70]
    DIRECTION INPUT ;
    PORT
      LAYER met2 ;
        RECT 386.430 0.000 386.710 4.000 ;
    END
  END la_data_in[70]
  PIN la_data_in[71]
    DIRECTION INPUT ;
    PORT
      LAYER met2 ;
        RECT 390.110 0.000 390.390 4.000 ;
    END
  END la_data_in[71]
  PIN la_data_in[72]
    DIRECTION INPUT ;
    PORT
      LAYER met2 ;
        RECT 393.790 0.000 394.070 4.000 ;
    END
  END la_data_in[72]
  PIN la_data_in[73]
    DIRECTION INPUT ;
    PORT
      LAYER met2 ;
        RECT 397.470 0.000 397.750 4.000 ;
    END
  END la_data_in[73]
  PIN la_data_in[74]
    DIRECTION INPUT ;
    PORT
      LAYER met2 ;
        RECT 401.150 0.000 401.430 4.000 ;
    END
  END la_data_in[74]
  PIN la_data_in[75]
    DIRECTION INPUT ;
    PORT
      LAYER met2 ;
        RECT 404.830 0.000 405.110 4.000 ;
    END
  END la_data_in[75]
  PIN la_data_in[76]
    DIRECTION INPUT ;
    PORT
      LAYER met2 ;
        RECT 408.510 0.000 408.790 4.000 ;
    END
  END la_data_in[76]
  PIN la_data_in[77]
    DIRECTION INPUT ;
    PORT
      LAYER met2 ;
        RECT 412.190 0.000 412.470 4.000 ;
    END
  END la_data_in[77]
  PIN la_data_in[78]
    DIRECTION INPUT ;
    PORT
      LAYER met2 ;
        RECT 415.870 0.000 416.150 4.000 ;
    END
  END la_data_in[78]
  PIN la_data_in[79]
    DIRECTION INPUT ;
    PORT
      LAYER met2 ;
        RECT 419.550 0.000 419.830 4.000 ;
    END
  END la_data_in[79]
  PIN la_data_in[7]
    DIRECTION INPUT ;
    PORT
      LAYER met2 ;
        RECT 155.050 0.000 155.330 4.000 ;
    END
  END la_data_in[7]
  PIN la_data_in[80]
    DIRECTION INPUT ;
    PORT
      LAYER met2 ;
        RECT 423.230 0.000 423.510 4.000 ;
    END
  END la_data_in[80]
  PIN la_data_in[81]
    DIRECTION INPUT ;
    PORT
      LAYER met2 ;
        RECT 426.910 0.000 427.190 4.000 ;
    END
  END la_data_in[81]
  PIN la_data_in[82]
    DIRECTION INPUT ;
    PORT
      LAYER met2 ;
        RECT 430.590 0.000 430.870 4.000 ;
    END
  END la_data_in[82]
  PIN la_data_in[83]
    DIRECTION INPUT ;
    PORT
      LAYER met2 ;
        RECT 434.270 0.000 434.550 4.000 ;
    END
  END la_data_in[83]
  PIN la_data_in[84]
    DIRECTION INPUT ;
    PORT
      LAYER met2 ;
        RECT 437.950 0.000 438.230 4.000 ;
    END
  END la_data_in[84]
  PIN la_data_in[85]
    DIRECTION INPUT ;
    PORT
      LAYER met2 ;
        RECT 441.630 0.000 441.910 4.000 ;
    END
  END la_data_in[85]
  PIN la_data_in[86]
    DIRECTION INPUT ;
    PORT
      LAYER met2 ;
        RECT 445.310 0.000 445.590 4.000 ;
    END
  END la_data_in[86]
  PIN la_data_in[87]
    DIRECTION INPUT ;
    PORT
      LAYER met2 ;
        RECT 448.990 0.000 449.270 4.000 ;
    END
  END la_data_in[87]
  PIN la_data_in[88]
    DIRECTION INPUT ;
    PORT
      LAYER met2 ;
        RECT 452.670 0.000 452.950 4.000 ;
    END
  END la_data_in[88]
  PIN la_data_in[89]
    DIRECTION INPUT ;
    PORT
      LAYER met2 ;
        RECT 456.350 0.000 456.630 4.000 ;
    END
  END la_data_in[89]
  PIN la_data_in[8]
    DIRECTION INPUT ;
    PORT
      LAYER met2 ;
        RECT 158.730 0.000 159.010 4.000 ;
    END
  END la_data_in[8]
  PIN la_data_in[90]
    DIRECTION INPUT ;
    PORT
      LAYER met2 ;
        RECT 460.030 0.000 460.310 4.000 ;
    END
  END la_data_in[90]
  PIN la_data_in[91]
    DIRECTION INPUT ;
    PORT
      LAYER met2 ;
        RECT 463.710 0.000 463.990 4.000 ;
    END
  END la_data_in[91]
  PIN la_data_in[92]
    DIRECTION INPUT ;
    PORT
      LAYER met2 ;
        RECT 467.390 0.000 467.670 4.000 ;
    END
  END la_data_in[92]
  PIN la_data_in[93]
    DIRECTION INPUT ;
    PORT
      LAYER met2 ;
        RECT 471.070 0.000 471.350 4.000 ;
    END
  END la_data_in[93]
  PIN la_data_in[94]
    DIRECTION INPUT ;
    PORT
      LAYER met2 ;
        RECT 474.750 0.000 475.030 4.000 ;
    END
  END la_data_in[94]
  PIN la_data_in[95]
    DIRECTION INPUT ;
    PORT
      LAYER met2 ;
        RECT 478.430 0.000 478.710 4.000 ;
    END
  END la_data_in[95]
  PIN la_data_in[96]
    DIRECTION INPUT ;
    PORT
      LAYER met2 ;
        RECT 482.110 0.000 482.390 4.000 ;
    END
  END la_data_in[96]
  PIN la_data_in[97]
    DIRECTION INPUT ;
    PORT
      LAYER met2 ;
        RECT 485.790 0.000 486.070 4.000 ;
    END
  END la_data_in[97]
  PIN la_data_in[98]
    DIRECTION INPUT ;
    PORT
      LAYER met2 ;
        RECT 489.470 0.000 489.750 4.000 ;
    END
  END la_data_in[98]
  PIN la_data_in[99]
    DIRECTION INPUT ;
    PORT
      LAYER met2 ;
        RECT 493.150 0.000 493.430 4.000 ;
    END
  END la_data_in[99]
  PIN la_data_in[9]
    DIRECTION INPUT ;
    PORT
      LAYER met2 ;
        RECT 162.410 0.000 162.690 4.000 ;
    END
  END la_data_in[9]
  PIN la_data_out[0]
    DIRECTION OUTPUT TRISTATE ;
    PORT
      LAYER met2 ;
        RECT 130.670 0.000 130.950 4.000 ;
    END
  END la_data_out[0]
  PIN la_data_out[100]
    DIRECTION OUTPUT TRISTATE ;
    PORT
      LAYER met2 ;
        RECT 498.210 0.000 498.490 4.000 ;
    END
  END la_data_out[100]
  PIN la_data_out[101]
    DIRECTION OUTPUT TRISTATE ;
    PORT
      LAYER met2 ;
        RECT 501.890 0.000 502.170 4.000 ;
    END
  END la_data_out[101]
  PIN la_data_out[102]
    DIRECTION OUTPUT TRISTATE ;
    PORT
      LAYER met2 ;
        RECT 505.570 0.000 505.850 4.000 ;
    END
  END la_data_out[102]
  PIN la_data_out[103]
    DIRECTION OUTPUT TRISTATE ;
    PORT
      LAYER met2 ;
        RECT 509.250 0.000 509.530 4.000 ;
    END
  END la_data_out[103]
  PIN la_data_out[104]
    DIRECTION OUTPUT TRISTATE ;
    PORT
      LAYER met2 ;
        RECT 512.930 0.000 513.210 4.000 ;
    END
  END la_data_out[104]
  PIN la_data_out[105]
    DIRECTION OUTPUT TRISTATE ;
    PORT
      LAYER met2 ;
        RECT 516.610 0.000 516.890 4.000 ;
    END
  END la_data_out[105]
  PIN la_data_out[106]
    DIRECTION OUTPUT TRISTATE ;
    PORT
      LAYER met2 ;
        RECT 520.290 0.000 520.570 4.000 ;
    END
  END la_data_out[106]
  PIN la_data_out[107]
    DIRECTION OUTPUT TRISTATE ;
    PORT
      LAYER met2 ;
        RECT 523.970 0.000 524.250 4.000 ;
    END
  END la_data_out[107]
  PIN la_data_out[108]
    DIRECTION OUTPUT TRISTATE ;
    PORT
      LAYER met2 ;
        RECT 527.190 0.000 527.470 4.000 ;
    END
  END la_data_out[108]
  PIN la_data_out[109]
    DIRECTION OUTPUT TRISTATE ;
    PORT
      LAYER met2 ;
        RECT 530.870 0.000 531.150 4.000 ;
    END
  END la_data_out[109]
  PIN la_data_out[10]
    DIRECTION OUTPUT TRISTATE ;
    PORT
      LAYER met2 ;
        RECT 167.470 0.000 167.750 4.000 ;
    END
  END la_data_out[10]
  PIN la_data_out[110]
    DIRECTION OUTPUT TRISTATE ;
    PORT
      LAYER met2 ;
        RECT 534.550 0.000 534.830 4.000 ;
    END
  END la_data_out[110]
  PIN la_data_out[111]
    DIRECTION OUTPUT TRISTATE ;
    PORT
      LAYER met2 ;
        RECT 538.230 0.000 538.510 4.000 ;
    END
  END la_data_out[111]
  PIN la_data_out[112]
    DIRECTION OUTPUT TRISTATE ;
    PORT
      LAYER met2 ;
        RECT 541.910 0.000 542.190 4.000 ;
    END
  END la_data_out[112]
  PIN la_data_out[113]
    DIRECTION OUTPUT TRISTATE ;
    PORT
      LAYER met2 ;
        RECT 545.590 0.000 545.870 4.000 ;
    END
  END la_data_out[113]
  PIN la_data_out[114]
    DIRECTION OUTPUT TRISTATE ;
    PORT
      LAYER met2 ;
        RECT 549.270 0.000 549.550 4.000 ;
    END
  END la_data_out[114]
  PIN la_data_out[115]
    DIRECTION OUTPUT TRISTATE ;
    PORT
      LAYER met2 ;
        RECT 552.950 0.000 553.230 4.000 ;
    END
  END la_data_out[115]
  PIN la_data_out[116]
    DIRECTION OUTPUT TRISTATE ;
    PORT
      LAYER met2 ;
        RECT 556.630 0.000 556.910 4.000 ;
    END
  END la_data_out[116]
  PIN la_data_out[117]
    DIRECTION OUTPUT TRISTATE ;
    PORT
      LAYER met2 ;
        RECT 560.310 0.000 560.590 4.000 ;
    END
  END la_data_out[117]
  PIN la_data_out[118]
    DIRECTION OUTPUT TRISTATE ;
    PORT
      LAYER met2 ;
        RECT 563.990 0.000 564.270 4.000 ;
    END
  END la_data_out[118]
  PIN la_data_out[119]
    DIRECTION OUTPUT TRISTATE ;
    PORT
      LAYER met2 ;
        RECT 567.670 0.000 567.950 4.000 ;
    END
  END la_data_out[119]
  PIN la_data_out[11]
    DIRECTION OUTPUT TRISTATE ;
    PORT
      LAYER met2 ;
        RECT 171.150 0.000 171.430 4.000 ;
    END
  END la_data_out[11]
  PIN la_data_out[120]
    DIRECTION OUTPUT TRISTATE ;
    PORT
      LAYER met2 ;
        RECT 571.350 0.000 571.630 4.000 ;
    END
  END la_data_out[120]
  PIN la_data_out[121]
    DIRECTION OUTPUT TRISTATE ;
    PORT
      LAYER met2 ;
        RECT 575.030 0.000 575.310 4.000 ;
    END
  END la_data_out[121]
  PIN la_data_out[122]
    DIRECTION OUTPUT TRISTATE ;
    PORT
      LAYER met2 ;
        RECT 578.710 0.000 578.990 4.000 ;
    END
  END la_data_out[122]
  PIN la_data_out[123]
    DIRECTION OUTPUT TRISTATE ;
    PORT
      LAYER met2 ;
        RECT 582.390 0.000 582.670 4.000 ;
    END
  END la_data_out[123]
  PIN la_data_out[124]
    DIRECTION OUTPUT TRISTATE ;
    PORT
      LAYER met2 ;
        RECT 586.070 0.000 586.350 4.000 ;
    END
  END la_data_out[124]
  PIN la_data_out[125]
    DIRECTION OUTPUT TRISTATE ;
    PORT
      LAYER met2 ;
        RECT 589.750 0.000 590.030 4.000 ;
    END
  END la_data_out[125]
  PIN la_data_out[126]
    DIRECTION OUTPUT TRISTATE ;
    PORT
      LAYER met2 ;
        RECT 593.430 0.000 593.710 4.000 ;
    END
  END la_data_out[126]
  PIN la_data_out[127]
    DIRECTION OUTPUT TRISTATE ;
    PORT
      LAYER met2 ;
        RECT 597.110 0.000 597.390 4.000 ;
    END
  END la_data_out[127]
  PIN la_data_out[12]
    DIRECTION OUTPUT TRISTATE ;
    PORT
      LAYER met2 ;
        RECT 174.830 0.000 175.110 4.000 ;
    END
  END la_data_out[12]
  PIN la_data_out[13]
    DIRECTION OUTPUT TRISTATE ;
    PORT
      LAYER met2 ;
        RECT 178.510 0.000 178.790 4.000 ;
    END
  END la_data_out[13]
  PIN la_data_out[14]
    DIRECTION OUTPUT TRISTATE ;
    PORT
      LAYER met2 ;
        RECT 182.190 0.000 182.470 4.000 ;
    END
  END la_data_out[14]
  PIN la_data_out[15]
    DIRECTION OUTPUT TRISTATE ;
    PORT
      LAYER met2 ;
        RECT 185.870 0.000 186.150 4.000 ;
    END
  END la_data_out[15]
  PIN la_data_out[16]
    DIRECTION OUTPUT TRISTATE ;
    PORT
      LAYER met2 ;
        RECT 189.550 0.000 189.830 4.000 ;
    END
  END la_data_out[16]
  PIN la_data_out[17]
    DIRECTION OUTPUT TRISTATE ;
    PORT
      LAYER met2 ;
        RECT 193.230 0.000 193.510 4.000 ;
    END
  END la_data_out[17]
  PIN la_data_out[18]
    DIRECTION OUTPUT TRISTATE ;
    PORT
      LAYER met2 ;
        RECT 196.910 0.000 197.190 4.000 ;
    END
  END la_data_out[18]
  PIN la_data_out[19]
    DIRECTION OUTPUT TRISTATE ;
    PORT
      LAYER met2 ;
        RECT 200.590 0.000 200.870 4.000 ;
    END
  END la_data_out[19]
  PIN la_data_out[1]
    DIRECTION OUTPUT TRISTATE ;
    PORT
      LAYER met2 ;
        RECT 134.350 0.000 134.630 4.000 ;
    END
  END la_data_out[1]
  PIN la_data_out[20]
    DIRECTION OUTPUT TRISTATE ;
    PORT
      LAYER met2 ;
        RECT 204.270 0.000 204.550 4.000 ;
    END
  END la_data_out[20]
  PIN la_data_out[21]
    DIRECTION OUTPUT TRISTATE ;
    PORT
      LAYER met2 ;
        RECT 207.950 0.000 208.230 4.000 ;
    END
  END la_data_out[21]
  PIN la_data_out[22]
    DIRECTION OUTPUT TRISTATE ;
    PORT
      LAYER met2 ;
        RECT 211.630 0.000 211.910 4.000 ;
    END
  END la_data_out[22]
  PIN la_data_out[23]
    DIRECTION OUTPUT TRISTATE ;
    PORT
      LAYER met2 ;
        RECT 215.310 0.000 215.590 4.000 ;
    END
  END la_data_out[23]
  PIN la_data_out[24]
    DIRECTION OUTPUT TRISTATE ;
    PORT
      LAYER met2 ;
        RECT 218.990 0.000 219.270 4.000 ;
    END
  END la_data_out[24]
  PIN la_data_out[25]
    DIRECTION OUTPUT TRISTATE ;
    PORT
      LAYER met2 ;
        RECT 222.670 0.000 222.950 4.000 ;
    END
  END la_data_out[25]
  PIN la_data_out[26]
    DIRECTION OUTPUT TRISTATE ;
    PORT
      LAYER met2 ;
        RECT 226.350 0.000 226.630 4.000 ;
    END
  END la_data_out[26]
  PIN la_data_out[27]
    DIRECTION OUTPUT TRISTATE ;
    PORT
      LAYER met2 ;
        RECT 230.030 0.000 230.310 4.000 ;
    END
  END la_data_out[27]
  PIN la_data_out[28]
    DIRECTION OUTPUT TRISTATE ;
    PORT
      LAYER met2 ;
        RECT 233.710 0.000 233.990 4.000 ;
    END
  END la_data_out[28]
  PIN la_data_out[29]
    DIRECTION OUTPUT TRISTATE ;
    PORT
      LAYER met2 ;
        RECT 237.390 0.000 237.670 4.000 ;
    END
  END la_data_out[29]
  PIN la_data_out[2]
    DIRECTION OUTPUT TRISTATE ;
    PORT
      LAYER met2 ;
        RECT 138.030 0.000 138.310 4.000 ;
    END
  END la_data_out[2]
  PIN la_data_out[30]
    DIRECTION OUTPUT TRISTATE ;
    PORT
      LAYER met2 ;
        RECT 241.070 0.000 241.350 4.000 ;
    END
  END la_data_out[30]
  PIN la_data_out[31]
    DIRECTION OUTPUT TRISTATE ;
    PORT
      LAYER met2 ;
        RECT 244.750 0.000 245.030 4.000 ;
    END
  END la_data_out[31]
  PIN la_data_out[32]
    DIRECTION OUTPUT TRISTATE ;
    PORT
      LAYER met2 ;
        RECT 248.430 0.000 248.710 4.000 ;
    END
  END la_data_out[32]
  PIN la_data_out[33]
    DIRECTION OUTPUT TRISTATE ;
    PORT
      LAYER met2 ;
        RECT 252.110 0.000 252.390 4.000 ;
    END
  END la_data_out[33]
  PIN la_data_out[34]
    DIRECTION OUTPUT TRISTATE ;
    PORT
      LAYER met2 ;
        RECT 255.790 0.000 256.070 4.000 ;
    END
  END la_data_out[34]
  PIN la_data_out[35]
    DIRECTION OUTPUT TRISTATE ;
    PORT
      LAYER met2 ;
        RECT 259.470 0.000 259.750 4.000 ;
    END
  END la_data_out[35]
  PIN la_data_out[36]
    DIRECTION OUTPUT TRISTATE ;
    PORT
      LAYER met2 ;
        RECT 263.150 0.000 263.430 4.000 ;
    END
  END la_data_out[36]
  PIN la_data_out[37]
    DIRECTION OUTPUT TRISTATE ;
    PORT
      LAYER met2 ;
        RECT 266.830 0.000 267.110 4.000 ;
    END
  END la_data_out[37]
  PIN la_data_out[38]
    DIRECTION OUTPUT TRISTATE ;
    PORT
      LAYER met2 ;
        RECT 270.510 0.000 270.790 4.000 ;
    END
  END la_data_out[38]
  PIN la_data_out[39]
    DIRECTION OUTPUT TRISTATE ;
    PORT
      LAYER met2 ;
        RECT 274.190 0.000 274.470 4.000 ;
    END
  END la_data_out[39]
  PIN la_data_out[3]
    DIRECTION OUTPUT TRISTATE ;
    PORT
      LAYER met2 ;
        RECT 141.710 0.000 141.990 4.000 ;
    END
  END la_data_out[3]
  PIN la_data_out[40]
    DIRECTION OUTPUT TRISTATE ;
    PORT
      LAYER met2 ;
        RECT 277.870 0.000 278.150 4.000 ;
    END
  END la_data_out[40]
  PIN la_data_out[41]
    DIRECTION OUTPUT TRISTATE ;
    PORT
      LAYER met2 ;
        RECT 281.550 0.000 281.830 4.000 ;
    END
  END la_data_out[41]
  PIN la_data_out[42]
    DIRECTION OUTPUT TRISTATE ;
    PORT
      LAYER met2 ;
        RECT 285.230 0.000 285.510 4.000 ;
    END
  END la_data_out[42]
  PIN la_data_out[43]
    DIRECTION OUTPUT TRISTATE ;
    PORT
      LAYER met2 ;
        RECT 288.910 0.000 289.190 4.000 ;
    END
  END la_data_out[43]
  PIN la_data_out[44]
    DIRECTION OUTPUT TRISTATE ;
    PORT
      LAYER met2 ;
        RECT 292.590 0.000 292.870 4.000 ;
    END
  END la_data_out[44]
  PIN la_data_out[45]
    DIRECTION OUTPUT TRISTATE ;
    PORT
      LAYER met2 ;
        RECT 296.270 0.000 296.550 4.000 ;
    END
  END la_data_out[45]
  PIN la_data_out[46]
    DIRECTION OUTPUT TRISTATE ;
    PORT
      LAYER met2 ;
        RECT 299.950 0.000 300.230 4.000 ;
    END
  END la_data_out[46]
  PIN la_data_out[47]
    DIRECTION OUTPUT TRISTATE ;
    PORT
      LAYER met2 ;
        RECT 303.170 0.000 303.450 4.000 ;
    END
  END la_data_out[47]
  PIN la_data_out[48]
    DIRECTION OUTPUT TRISTATE ;
    PORT
      LAYER met2 ;
        RECT 306.850 0.000 307.130 4.000 ;
    END
  END la_data_out[48]
  PIN la_data_out[49]
    DIRECTION OUTPUT TRISTATE ;
    PORT
      LAYER met2 ;
        RECT 310.530 0.000 310.810 4.000 ;
    END
  END la_data_out[49]
  PIN la_data_out[4]
    DIRECTION OUTPUT TRISTATE ;
    PORT
      LAYER met2 ;
        RECT 145.390 0.000 145.670 4.000 ;
    END
  END la_data_out[4]
  PIN la_data_out[50]
    DIRECTION OUTPUT TRISTATE ;
    PORT
      LAYER met2 ;
        RECT 314.210 0.000 314.490 4.000 ;
    END
  END la_data_out[50]
  PIN la_data_out[51]
    DIRECTION OUTPUT TRISTATE ;
    PORT
      LAYER met2 ;
        RECT 317.890 0.000 318.170 4.000 ;
    END
  END la_data_out[51]
  PIN la_data_out[52]
    DIRECTION OUTPUT TRISTATE ;
    PORT
      LAYER met2 ;
        RECT 321.570 0.000 321.850 4.000 ;
    END
  END la_data_out[52]
  PIN la_data_out[53]
    DIRECTION OUTPUT TRISTATE ;
    PORT
      LAYER met2 ;
        RECT 325.250 0.000 325.530 4.000 ;
    END
  END la_data_out[53]
  PIN la_data_out[54]
    DIRECTION OUTPUT TRISTATE ;
    PORT
      LAYER met2 ;
        RECT 328.930 0.000 329.210 4.000 ;
    END
  END la_data_out[54]
  PIN la_data_out[55]
    DIRECTION OUTPUT TRISTATE ;
    PORT
      LAYER met2 ;
        RECT 332.610 0.000 332.890 4.000 ;
    END
  END la_data_out[55]
  PIN la_data_out[56]
    DIRECTION OUTPUT TRISTATE ;
    PORT
      LAYER met2 ;
        RECT 336.290 0.000 336.570 4.000 ;
    END
  END la_data_out[56]
  PIN la_data_out[57]
    DIRECTION OUTPUT TRISTATE ;
    PORT
      LAYER met2 ;
        RECT 339.970 0.000 340.250 4.000 ;
    END
  END la_data_out[57]
  PIN la_data_out[58]
    DIRECTION OUTPUT TRISTATE ;
    PORT
      LAYER met2 ;
        RECT 343.650 0.000 343.930 4.000 ;
    END
  END la_data_out[58]
  PIN la_data_out[59]
    DIRECTION OUTPUT TRISTATE ;
    PORT
      LAYER met2 ;
        RECT 347.330 0.000 347.610 4.000 ;
    END
  END la_data_out[59]
  PIN la_data_out[5]
    DIRECTION OUTPUT TRISTATE ;
    PORT
      LAYER met2 ;
        RECT 149.070 0.000 149.350 4.000 ;
    END
  END la_data_out[5]
  PIN la_data_out[60]
    DIRECTION OUTPUT TRISTATE ;
    PORT
      LAYER met2 ;
        RECT 351.010 0.000 351.290 4.000 ;
    END
  END la_data_out[60]
  PIN la_data_out[61]
    DIRECTION OUTPUT TRISTATE ;
    PORT
      LAYER met2 ;
        RECT 354.690 0.000 354.970 4.000 ;
    END
  END la_data_out[61]
  PIN la_data_out[62]
    DIRECTION OUTPUT TRISTATE ;
    PORT
      LAYER met2 ;
        RECT 358.370 0.000 358.650 4.000 ;
    END
  END la_data_out[62]
  PIN la_data_out[63]
    DIRECTION OUTPUT TRISTATE ;
    PORT
      LAYER met2 ;
        RECT 362.050 0.000 362.330 4.000 ;
    END
  END la_data_out[63]
  PIN la_data_out[64]
    DIRECTION OUTPUT TRISTATE ;
    PORT
      LAYER met2 ;
        RECT 365.730 0.000 366.010 4.000 ;
    END
  END la_data_out[64]
  PIN la_data_out[65]
    DIRECTION OUTPUT TRISTATE ;
    PORT
      LAYER met2 ;
        RECT 369.410 0.000 369.690 4.000 ;
    END
  END la_data_out[65]
  PIN la_data_out[66]
    DIRECTION OUTPUT TRISTATE ;
    PORT
      LAYER met2 ;
        RECT 373.090 0.000 373.370 4.000 ;
    END
  END la_data_out[66]
  PIN la_data_out[67]
    DIRECTION OUTPUT TRISTATE ;
    PORT
      LAYER met2 ;
        RECT 376.770 0.000 377.050 4.000 ;
    END
  END la_data_out[67]
  PIN la_data_out[68]
    DIRECTION OUTPUT TRISTATE ;
    PORT
      LAYER met2 ;
        RECT 380.450 0.000 380.730 4.000 ;
    END
  END la_data_out[68]
  PIN la_data_out[69]
    DIRECTION OUTPUT TRISTATE ;
    PORT
      LAYER met2 ;
        RECT 384.130 0.000 384.410 4.000 ;
    END
  END la_data_out[69]
  PIN la_data_out[6]
    DIRECTION OUTPUT TRISTATE ;
    PORT
      LAYER met2 ;
        RECT 152.750 0.000 153.030 4.000 ;
    END
  END la_data_out[6]
  PIN la_data_out[70]
    DIRECTION OUTPUT TRISTATE ;
    PORT
      LAYER met2 ;
        RECT 387.810 0.000 388.090 4.000 ;
    END
  END la_data_out[70]
  PIN la_data_out[71]
    DIRECTION OUTPUT TRISTATE ;
    PORT
      LAYER met2 ;
        RECT 391.490 0.000 391.770 4.000 ;
    END
  END la_data_out[71]
  PIN la_data_out[72]
    DIRECTION OUTPUT TRISTATE ;
    PORT
      LAYER met2 ;
        RECT 395.170 0.000 395.450 4.000 ;
    END
  END la_data_out[72]
  PIN la_data_out[73]
    DIRECTION OUTPUT TRISTATE ;
    PORT
      LAYER met2 ;
        RECT 398.850 0.000 399.130 4.000 ;
    END
  END la_data_out[73]
  PIN la_data_out[74]
    DIRECTION OUTPUT TRISTATE ;
    PORT
      LAYER met2 ;
        RECT 402.530 0.000 402.810 4.000 ;
    END
  END la_data_out[74]
  PIN la_data_out[75]
    DIRECTION OUTPUT TRISTATE ;
    PORT
      LAYER met2 ;
        RECT 406.210 0.000 406.490 4.000 ;
    END
  END la_data_out[75]
  PIN la_data_out[76]
    DIRECTION OUTPUT TRISTATE ;
    PORT
      LAYER met2 ;
        RECT 409.890 0.000 410.170 4.000 ;
    END
  END la_data_out[76]
  PIN la_data_out[77]
    DIRECTION OUTPUT TRISTATE ;
    PORT
      LAYER met2 ;
        RECT 413.570 0.000 413.850 4.000 ;
    END
  END la_data_out[77]
  PIN la_data_out[78]
    DIRECTION OUTPUT TRISTATE ;
    PORT
      LAYER met2 ;
        RECT 417.250 0.000 417.530 4.000 ;
    END
  END la_data_out[78]
  PIN la_data_out[79]
    DIRECTION OUTPUT TRISTATE ;
    PORT
      LAYER met2 ;
        RECT 420.930 0.000 421.210 4.000 ;
    END
  END la_data_out[79]
  PIN la_data_out[7]
    DIRECTION OUTPUT TRISTATE ;
    PORT
      LAYER met2 ;
        RECT 156.430 0.000 156.710 4.000 ;
    END
  END la_data_out[7]
  PIN la_data_out[80]
    DIRECTION OUTPUT TRISTATE ;
    PORT
      LAYER met2 ;
        RECT 424.610 0.000 424.890 4.000 ;
    END
  END la_data_out[80]
  PIN la_data_out[81]
    DIRECTION OUTPUT TRISTATE ;
    PORT
      LAYER met2 ;
        RECT 428.290 0.000 428.570 4.000 ;
    END
  END la_data_out[81]
  PIN la_data_out[82]
    DIRECTION OUTPUT TRISTATE ;
    PORT
      LAYER met2 ;
        RECT 431.970 0.000 432.250 4.000 ;
    END
  END la_data_out[82]
  PIN la_data_out[83]
    DIRECTION OUTPUT TRISTATE ;
    PORT
      LAYER met2 ;
        RECT 435.650 0.000 435.930 4.000 ;
    END
  END la_data_out[83]
  PIN la_data_out[84]
    DIRECTION OUTPUT TRISTATE ;
    PORT
      LAYER met2 ;
        RECT 439.330 0.000 439.610 4.000 ;
    END
  END la_data_out[84]
  PIN la_data_out[85]
    DIRECTION OUTPUT TRISTATE ;
    PORT
      LAYER met2 ;
        RECT 443.010 0.000 443.290 4.000 ;
    END
  END la_data_out[85]
  PIN la_data_out[86]
    DIRECTION OUTPUT TRISTATE ;
    PORT
      LAYER met2 ;
        RECT 446.690 0.000 446.970 4.000 ;
    END
  END la_data_out[86]
  PIN la_data_out[87]
    DIRECTION OUTPUT TRISTATE ;
    PORT
      LAYER met2 ;
        RECT 450.370 0.000 450.650 4.000 ;
    END
  END la_data_out[87]
  PIN la_data_out[88]
    DIRECTION OUTPUT TRISTATE ;
    PORT
      LAYER met2 ;
        RECT 454.050 0.000 454.330 4.000 ;
    END
  END la_data_out[88]
  PIN la_data_out[89]
    DIRECTION OUTPUT TRISTATE ;
    PORT
      LAYER met2 ;
        RECT 457.730 0.000 458.010 4.000 ;
    END
  END la_data_out[89]
  PIN la_data_out[8]
    DIRECTION OUTPUT TRISTATE ;
    PORT
      LAYER met2 ;
        RECT 160.110 0.000 160.390 4.000 ;
    END
  END la_data_out[8]
  PIN la_data_out[90]
    DIRECTION OUTPUT TRISTATE ;
    PORT
      LAYER met2 ;
        RECT 461.410 0.000 461.690 4.000 ;
    END
  END la_data_out[90]
  PIN la_data_out[91]
    DIRECTION OUTPUT TRISTATE ;
    PORT
      LAYER met2 ;
        RECT 465.090 0.000 465.370 4.000 ;
    END
  END la_data_out[91]
  PIN la_data_out[92]
    DIRECTION OUTPUT TRISTATE ;
    PORT
      LAYER met2 ;
        RECT 468.770 0.000 469.050 4.000 ;
    END
  END la_data_out[92]
  PIN la_data_out[93]
    DIRECTION OUTPUT TRISTATE ;
    PORT
      LAYER met2 ;
        RECT 472.450 0.000 472.730 4.000 ;
    END
  END la_data_out[93]
  PIN la_data_out[94]
    DIRECTION OUTPUT TRISTATE ;
    PORT
      LAYER met2 ;
        RECT 476.130 0.000 476.410 4.000 ;
    END
  END la_data_out[94]
  PIN la_data_out[95]
    DIRECTION OUTPUT TRISTATE ;
    PORT
      LAYER met2 ;
        RECT 479.810 0.000 480.090 4.000 ;
    END
  END la_data_out[95]
  PIN la_data_out[96]
    DIRECTION OUTPUT TRISTATE ;
    PORT
      LAYER met2 ;
        RECT 483.490 0.000 483.770 4.000 ;
    END
  END la_data_out[96]
  PIN la_data_out[97]
    DIRECTION OUTPUT TRISTATE ;
    PORT
      LAYER met2 ;
        RECT 487.170 0.000 487.450 4.000 ;
    END
  END la_data_out[97]
  PIN la_data_out[98]
    DIRECTION OUTPUT TRISTATE ;
    PORT
      LAYER met2 ;
        RECT 490.850 0.000 491.130 4.000 ;
    END
  END la_data_out[98]
  PIN la_data_out[99]
    DIRECTION OUTPUT TRISTATE ;
    PORT
      LAYER met2 ;
        RECT 494.530 0.000 494.810 4.000 ;
    END
  END la_data_out[99]
  PIN la_data_out[9]
    DIRECTION OUTPUT TRISTATE ;
    PORT
      LAYER met2 ;
        RECT 163.790 0.000 164.070 4.000 ;
    END
  END la_data_out[9]
  PIN la_oen[0]
    DIRECTION INPUT ;
    PORT
      LAYER met2 ;
        RECT 132.050 0.000 132.330 4.000 ;
    END
  END la_oen[0]
  PIN la_oen[100]
    DIRECTION INPUT ;
    PORT
      LAYER met2 ;
        RECT 499.130 0.000 499.410 4.000 ;
    END
  END la_oen[100]
  PIN la_oen[101]
    DIRECTION INPUT ;
    PORT
      LAYER met2 ;
        RECT 502.810 0.000 503.090 4.000 ;
    END
  END la_oen[101]
  PIN la_oen[102]
    DIRECTION INPUT ;
    PORT
      LAYER met2 ;
        RECT 506.490 0.000 506.770 4.000 ;
    END
  END la_oen[102]
  PIN la_oen[103]
    DIRECTION INPUT ;
    PORT
      LAYER met2 ;
        RECT 510.170 0.000 510.450 4.000 ;
    END
  END la_oen[103]
  PIN la_oen[104]
    DIRECTION INPUT ;
    PORT
      LAYER met2 ;
        RECT 513.850 0.000 514.130 4.000 ;
    END
  END la_oen[104]
  PIN la_oen[105]
    DIRECTION INPUT ;
    PORT
      LAYER met2 ;
        RECT 517.530 0.000 517.810 4.000 ;
    END
  END la_oen[105]
  PIN la_oen[106]
    DIRECTION INPUT ;
    PORT
      LAYER met2 ;
        RECT 521.210 0.000 521.490 4.000 ;
    END
  END la_oen[106]
  PIN la_oen[107]
    DIRECTION INPUT ;
    PORT
      LAYER met2 ;
        RECT 524.890 0.000 525.170 4.000 ;
    END
  END la_oen[107]
  PIN la_oen[108]
    DIRECTION INPUT ;
    PORT
      LAYER met2 ;
        RECT 528.570 0.000 528.850 4.000 ;
    END
  END la_oen[108]
  PIN la_oen[109]
    DIRECTION INPUT ;
    PORT
      LAYER met2 ;
        RECT 532.250 0.000 532.530 4.000 ;
    END
  END la_oen[109]
  PIN la_oen[10]
    DIRECTION INPUT ;
    PORT
      LAYER met2 ;
        RECT 168.850 0.000 169.130 4.000 ;
    END
  END la_oen[10]
  PIN la_oen[110]
    DIRECTION INPUT ;
    PORT
      LAYER met2 ;
        RECT 535.930 0.000 536.210 4.000 ;
    END
  END la_oen[110]
  PIN la_oen[111]
    DIRECTION INPUT ;
    PORT
      LAYER met2 ;
        RECT 539.610 0.000 539.890 4.000 ;
    END
  END la_oen[111]
  PIN la_oen[112]
    DIRECTION INPUT ;
    PORT
      LAYER met2 ;
        RECT 543.290 0.000 543.570 4.000 ;
    END
  END la_oen[112]
  PIN la_oen[113]
    DIRECTION INPUT ;
    PORT
      LAYER met2 ;
        RECT 546.970 0.000 547.250 4.000 ;
    END
  END la_oen[113]
  PIN la_oen[114]
    DIRECTION INPUT ;
    PORT
      LAYER met2 ;
        RECT 550.650 0.000 550.930 4.000 ;
    END
  END la_oen[114]
  PIN la_oen[115]
    DIRECTION INPUT ;
    PORT
      LAYER met2 ;
        RECT 554.330 0.000 554.610 4.000 ;
    END
  END la_oen[115]
  PIN la_oen[116]
    DIRECTION INPUT ;
    PORT
      LAYER met2 ;
        RECT 558.010 0.000 558.290 4.000 ;
    END
  END la_oen[116]
  PIN la_oen[117]
    DIRECTION INPUT ;
    PORT
      LAYER met2 ;
        RECT 561.690 0.000 561.970 4.000 ;
    END
  END la_oen[117]
  PIN la_oen[118]
    DIRECTION INPUT ;
    PORT
      LAYER met2 ;
        RECT 565.370 0.000 565.650 4.000 ;
    END
  END la_oen[118]
  PIN la_oen[119]
    DIRECTION INPUT ;
    PORT
      LAYER met2 ;
        RECT 569.050 0.000 569.330 4.000 ;
    END
  END la_oen[119]
  PIN la_oen[11]
    DIRECTION INPUT ;
    PORT
      LAYER met2 ;
        RECT 172.530 0.000 172.810 4.000 ;
    END
  END la_oen[11]
  PIN la_oen[120]
    DIRECTION INPUT ;
    PORT
      LAYER met2 ;
        RECT 572.730 0.000 573.010 4.000 ;
    END
  END la_oen[120]
  PIN la_oen[121]
    DIRECTION INPUT ;
    PORT
      LAYER met2 ;
        RECT 576.410 0.000 576.690 4.000 ;
    END
  END la_oen[121]
  PIN la_oen[122]
    DIRECTION INPUT ;
    PORT
      LAYER met2 ;
        RECT 580.090 0.000 580.370 4.000 ;
    END
  END la_oen[122]
  PIN la_oen[123]
    DIRECTION INPUT ;
    PORT
      LAYER met2 ;
        RECT 583.770 0.000 584.050 4.000 ;
    END
  END la_oen[123]
  PIN la_oen[124]
    DIRECTION INPUT ;
    PORT
      LAYER met2 ;
        RECT 587.450 0.000 587.730 4.000 ;
    END
  END la_oen[124]
  PIN la_oen[125]
    DIRECTION INPUT ;
    PORT
      LAYER met2 ;
        RECT 591.130 0.000 591.410 4.000 ;
    END
  END la_oen[125]
  PIN la_oen[126]
    DIRECTION INPUT ;
    PORT
      LAYER met2 ;
        RECT 594.810 0.000 595.090 4.000 ;
    END
  END la_oen[126]
  PIN la_oen[127]
    DIRECTION INPUT ;
    PORT
      LAYER met2 ;
        RECT 598.490 0.000 598.770 4.000 ;
    END
  END la_oen[127]
  PIN la_oen[12]
    DIRECTION INPUT ;
    PORT
      LAYER met2 ;
        RECT 176.210 0.000 176.490 4.000 ;
    END
  END la_oen[12]
  PIN la_oen[13]
    DIRECTION INPUT ;
    PORT
      LAYER met2 ;
        RECT 179.890 0.000 180.170 4.000 ;
    END
  END la_oen[13]
  PIN la_oen[14]
    DIRECTION INPUT ;
    PORT
      LAYER met2 ;
        RECT 183.570 0.000 183.850 4.000 ;
    END
  END la_oen[14]
  PIN la_oen[15]
    DIRECTION INPUT ;
    PORT
      LAYER met2 ;
        RECT 187.250 0.000 187.530 4.000 ;
    END
  END la_oen[15]
  PIN la_oen[16]
    DIRECTION INPUT ;
    PORT
      LAYER met2 ;
        RECT 190.930 0.000 191.210 4.000 ;
    END
  END la_oen[16]
  PIN la_oen[17]
    DIRECTION INPUT ;
    PORT
      LAYER met2 ;
        RECT 194.610 0.000 194.890 4.000 ;
    END
  END la_oen[17]
  PIN la_oen[18]
    DIRECTION INPUT ;
    PORT
      LAYER met2 ;
        RECT 198.290 0.000 198.570 4.000 ;
    END
  END la_oen[18]
  PIN la_oen[19]
    DIRECTION INPUT ;
    PORT
      LAYER met2 ;
        RECT 201.970 0.000 202.250 4.000 ;
    END
  END la_oen[19]
  PIN la_oen[1]
    DIRECTION INPUT ;
    PORT
      LAYER met2 ;
        RECT 135.730 0.000 136.010 4.000 ;
    END
  END la_oen[1]
  PIN la_oen[20]
    DIRECTION INPUT ;
    PORT
      LAYER met2 ;
        RECT 205.650 0.000 205.930 4.000 ;
    END
  END la_oen[20]
  PIN la_oen[21]
    DIRECTION INPUT ;
    PORT
      LAYER met2 ;
        RECT 209.330 0.000 209.610 4.000 ;
    END
  END la_oen[21]
  PIN la_oen[22]
    DIRECTION INPUT ;
    PORT
      LAYER met2 ;
        RECT 213.010 0.000 213.290 4.000 ;
    END
  END la_oen[22]
  PIN la_oen[23]
    DIRECTION INPUT ;
    PORT
      LAYER met2 ;
        RECT 216.690 0.000 216.970 4.000 ;
    END
  END la_oen[23]
  PIN la_oen[24]
    DIRECTION INPUT ;
    PORT
      LAYER met2 ;
        RECT 220.370 0.000 220.650 4.000 ;
    END
  END la_oen[24]
  PIN la_oen[25]
    DIRECTION INPUT ;
    PORT
      LAYER met2 ;
        RECT 224.050 0.000 224.330 4.000 ;
    END
  END la_oen[25]
  PIN la_oen[26]
    DIRECTION INPUT ;
    PORT
      LAYER met2 ;
        RECT 227.270 0.000 227.550 4.000 ;
    END
  END la_oen[26]
  PIN la_oen[27]
    DIRECTION INPUT ;
    PORT
      LAYER met2 ;
        RECT 230.950 0.000 231.230 4.000 ;
    END
  END la_oen[27]
  PIN la_oen[28]
    DIRECTION INPUT ;
    PORT
      LAYER met2 ;
        RECT 234.630 0.000 234.910 4.000 ;
    END
  END la_oen[28]
  PIN la_oen[29]
    DIRECTION INPUT ;
    PORT
      LAYER met2 ;
        RECT 238.310 0.000 238.590 4.000 ;
    END
  END la_oen[29]
  PIN la_oen[2]
    DIRECTION INPUT ;
    PORT
      LAYER met2 ;
        RECT 139.410 0.000 139.690 4.000 ;
    END
  END la_oen[2]
  PIN la_oen[30]
    DIRECTION INPUT ;
    PORT
      LAYER met2 ;
        RECT 241.990 0.000 242.270 4.000 ;
    END
  END la_oen[30]
  PIN la_oen[31]
    DIRECTION INPUT ;
    PORT
      LAYER met2 ;
        RECT 245.670 0.000 245.950 4.000 ;
    END
  END la_oen[31]
  PIN la_oen[32]
    DIRECTION INPUT ;
    PORT
      LAYER met2 ;
        RECT 249.350 0.000 249.630 4.000 ;
    END
  END la_oen[32]
  PIN la_oen[33]
    DIRECTION INPUT ;
    PORT
      LAYER met2 ;
        RECT 253.030 0.000 253.310 4.000 ;
    END
  END la_oen[33]
  PIN la_oen[34]
    DIRECTION INPUT ;
    PORT
      LAYER met2 ;
        RECT 256.710 0.000 256.990 4.000 ;
    END
  END la_oen[34]
  PIN la_oen[35]
    DIRECTION INPUT ;
    PORT
      LAYER met2 ;
        RECT 260.390 0.000 260.670 4.000 ;
    END
  END la_oen[35]
  PIN la_oen[36]
    DIRECTION INPUT ;
    PORT
      LAYER met2 ;
        RECT 264.070 0.000 264.350 4.000 ;
    END
  END la_oen[36]
  PIN la_oen[37]
    DIRECTION INPUT ;
    PORT
      LAYER met2 ;
        RECT 267.750 0.000 268.030 4.000 ;
    END
  END la_oen[37]
  PIN la_oen[38]
    DIRECTION INPUT ;
    PORT
      LAYER met2 ;
        RECT 271.430 0.000 271.710 4.000 ;
    END
  END la_oen[38]
  PIN la_oen[39]
    DIRECTION INPUT ;
    PORT
      LAYER met2 ;
        RECT 275.110 0.000 275.390 4.000 ;
    END
  END la_oen[39]
  PIN la_oen[3]
    DIRECTION INPUT ;
    PORT
      LAYER met2 ;
        RECT 143.090 0.000 143.370 4.000 ;
    END
  END la_oen[3]
  PIN la_oen[40]
    DIRECTION INPUT ;
    PORT
      LAYER met2 ;
        RECT 278.790 0.000 279.070 4.000 ;
    END
  END la_oen[40]
  PIN la_oen[41]
    DIRECTION INPUT ;
    PORT
      LAYER met2 ;
        RECT 282.470 0.000 282.750 4.000 ;
    END
  END la_oen[41]
  PIN la_oen[42]
    DIRECTION INPUT ;
    PORT
      LAYER met2 ;
        RECT 286.150 0.000 286.430 4.000 ;
    END
  END la_oen[42]
  PIN la_oen[43]
    DIRECTION INPUT ;
    PORT
      LAYER met2 ;
        RECT 289.830 0.000 290.110 4.000 ;
    END
  END la_oen[43]
  PIN la_oen[44]
    DIRECTION INPUT ;
    PORT
      LAYER met2 ;
        RECT 293.510 0.000 293.790 4.000 ;
    END
  END la_oen[44]
  PIN la_oen[45]
    DIRECTION INPUT ;
    PORT
      LAYER met2 ;
        RECT 297.190 0.000 297.470 4.000 ;
    END
  END la_oen[45]
  PIN la_oen[46]
    DIRECTION INPUT ;
    PORT
      LAYER met2 ;
        RECT 300.870 0.000 301.150 4.000 ;
    END
  END la_oen[46]
  PIN la_oen[47]
    DIRECTION INPUT ;
    PORT
      LAYER met2 ;
        RECT 304.550 0.000 304.830 4.000 ;
    END
  END la_oen[47]
  PIN la_oen[48]
    DIRECTION INPUT ;
    PORT
      LAYER met2 ;
        RECT 308.230 0.000 308.510 4.000 ;
    END
  END la_oen[48]
  PIN la_oen[49]
    DIRECTION INPUT ;
    PORT
      LAYER met2 ;
        RECT 311.910 0.000 312.190 4.000 ;
    END
  END la_oen[49]
  PIN la_oen[4]
    DIRECTION INPUT ;
    PORT
      LAYER met2 ;
        RECT 146.770 0.000 147.050 4.000 ;
    END
  END la_oen[4]
  PIN la_oen[50]
    DIRECTION INPUT ;
    PORT
      LAYER met2 ;
        RECT 315.590 0.000 315.870 4.000 ;
    END
  END la_oen[50]
  PIN la_oen[51]
    DIRECTION INPUT ;
    PORT
      LAYER met2 ;
        RECT 319.270 0.000 319.550 4.000 ;
    END
  END la_oen[51]
  PIN la_oen[52]
    DIRECTION INPUT ;
    PORT
      LAYER met2 ;
        RECT 322.950 0.000 323.230 4.000 ;
    END
  END la_oen[52]
  PIN la_oen[53]
    DIRECTION INPUT ;
    PORT
      LAYER met2 ;
        RECT 326.630 0.000 326.910 4.000 ;
    END
  END la_oen[53]
  PIN la_oen[54]
    DIRECTION INPUT ;
    PORT
      LAYER met2 ;
        RECT 330.310 0.000 330.590 4.000 ;
    END
  END la_oen[54]
  PIN la_oen[55]
    DIRECTION INPUT ;
    PORT
      LAYER met2 ;
        RECT 333.990 0.000 334.270 4.000 ;
    END
  END la_oen[55]
  PIN la_oen[56]
    DIRECTION INPUT ;
    PORT
      LAYER met2 ;
        RECT 337.670 0.000 337.950 4.000 ;
    END
  END la_oen[56]
  PIN la_oen[57]
    DIRECTION INPUT ;
    PORT
      LAYER met2 ;
        RECT 341.350 0.000 341.630 4.000 ;
    END
  END la_oen[57]
  PIN la_oen[58]
    DIRECTION INPUT ;
    PORT
      LAYER met2 ;
        RECT 345.030 0.000 345.310 4.000 ;
    END
  END la_oen[58]
  PIN la_oen[59]
    DIRECTION INPUT ;
    PORT
      LAYER met2 ;
        RECT 348.710 0.000 348.990 4.000 ;
    END
  END la_oen[59]
  PIN la_oen[5]
    DIRECTION INPUT ;
    PORT
      LAYER met2 ;
        RECT 150.450 0.000 150.730 4.000 ;
    END
  END la_oen[5]
  PIN la_oen[60]
    DIRECTION INPUT ;
    PORT
      LAYER met2 ;
        RECT 352.390 0.000 352.670 4.000 ;
    END
  END la_oen[60]
  PIN la_oen[61]
    DIRECTION INPUT ;
    PORT
      LAYER met2 ;
        RECT 356.070 0.000 356.350 4.000 ;
    END
  END la_oen[61]
  PIN la_oen[62]
    DIRECTION INPUT ;
    PORT
      LAYER met2 ;
        RECT 359.750 0.000 360.030 4.000 ;
    END
  END la_oen[62]
  PIN la_oen[63]
    DIRECTION INPUT ;
    PORT
      LAYER met2 ;
        RECT 363.430 0.000 363.710 4.000 ;
    END
  END la_oen[63]
  PIN la_oen[64]
    DIRECTION INPUT ;
    PORT
      LAYER met2 ;
        RECT 367.110 0.000 367.390 4.000 ;
    END
  END la_oen[64]
  PIN la_oen[65]
    DIRECTION INPUT ;
    PORT
      LAYER met2 ;
        RECT 370.790 0.000 371.070 4.000 ;
    END
  END la_oen[65]
  PIN la_oen[66]
    DIRECTION INPUT ;
    PORT
      LAYER met2 ;
        RECT 374.470 0.000 374.750 4.000 ;
    END
  END la_oen[66]
  PIN la_oen[67]
    DIRECTION INPUT ;
    PORT
      LAYER met2 ;
        RECT 378.150 0.000 378.430 4.000 ;
    END
  END la_oen[67]
  PIN la_oen[68]
    DIRECTION INPUT ;
    PORT
      LAYER met2 ;
        RECT 381.830 0.000 382.110 4.000 ;
    END
  END la_oen[68]
  PIN la_oen[69]
    DIRECTION INPUT ;
    PORT
      LAYER met2 ;
        RECT 385.510 0.000 385.790 4.000 ;
    END
  END la_oen[69]
  PIN la_oen[6]
    DIRECTION INPUT ;
    PORT
      LAYER met2 ;
        RECT 154.130 0.000 154.410 4.000 ;
    END
  END la_oen[6]
  PIN la_oen[70]
    DIRECTION INPUT ;
    PORT
      LAYER met2 ;
        RECT 389.190 0.000 389.470 4.000 ;
    END
  END la_oen[70]
  PIN la_oen[71]
    DIRECTION INPUT ;
    PORT
      LAYER met2 ;
        RECT 392.870 0.000 393.150 4.000 ;
    END
  END la_oen[71]
  PIN la_oen[72]
    DIRECTION INPUT ;
    PORT
      LAYER met2 ;
        RECT 396.550 0.000 396.830 4.000 ;
    END
  END la_oen[72]
  PIN la_oen[73]
    DIRECTION INPUT ;
    PORT
      LAYER met2 ;
        RECT 400.230 0.000 400.510 4.000 ;
    END
  END la_oen[73]
  PIN la_oen[74]
    DIRECTION INPUT ;
    PORT
      LAYER met2 ;
        RECT 403.910 0.000 404.190 4.000 ;
    END
  END la_oen[74]
  PIN la_oen[75]
    DIRECTION INPUT ;
    PORT
      LAYER met2 ;
        RECT 407.590 0.000 407.870 4.000 ;
    END
  END la_oen[75]
  PIN la_oen[76]
    DIRECTION INPUT ;
    PORT
      LAYER met2 ;
        RECT 411.270 0.000 411.550 4.000 ;
    END
  END la_oen[76]
  PIN la_oen[77]
    DIRECTION INPUT ;
    PORT
      LAYER met2 ;
        RECT 414.950 0.000 415.230 4.000 ;
    END
  END la_oen[77]
  PIN la_oen[78]
    DIRECTION INPUT ;
    PORT
      LAYER met2 ;
        RECT 418.630 0.000 418.910 4.000 ;
    END
  END la_oen[78]
  PIN la_oen[79]
    DIRECTION INPUT ;
    PORT
      LAYER met2 ;
        RECT 422.310 0.000 422.590 4.000 ;
    END
  END la_oen[79]
  PIN la_oen[7]
    DIRECTION INPUT ;
    PORT
      LAYER met2 ;
        RECT 157.810 0.000 158.090 4.000 ;
    END
  END la_oen[7]
  PIN la_oen[80]
    DIRECTION INPUT ;
    PORT
      LAYER met2 ;
        RECT 425.990 0.000 426.270 4.000 ;
    END
  END la_oen[80]
  PIN la_oen[81]
    DIRECTION INPUT ;
    PORT
      LAYER met2 ;
        RECT 429.670 0.000 429.950 4.000 ;
    END
  END la_oen[81]
  PIN la_oen[82]
    DIRECTION INPUT ;
    PORT
      LAYER met2 ;
        RECT 433.350 0.000 433.630 4.000 ;
    END
  END la_oen[82]
  PIN la_oen[83]
    DIRECTION INPUT ;
    PORT
      LAYER met2 ;
        RECT 437.030 0.000 437.310 4.000 ;
    END
  END la_oen[83]
  PIN la_oen[84]
    DIRECTION INPUT ;
    PORT
      LAYER met2 ;
        RECT 440.710 0.000 440.990 4.000 ;
    END
  END la_oen[84]
  PIN la_oen[85]
    DIRECTION INPUT ;
    PORT
      LAYER met2 ;
        RECT 444.390 0.000 444.670 4.000 ;
    END
  END la_oen[85]
  PIN la_oen[86]
    DIRECTION INPUT ;
    PORT
      LAYER met2 ;
        RECT 448.070 0.000 448.350 4.000 ;
    END
  END la_oen[86]
  PIN la_oen[87]
    DIRECTION INPUT ;
    PORT
      LAYER met2 ;
        RECT 451.290 0.000 451.570 4.000 ;
    END
  END la_oen[87]
  PIN la_oen[88]
    DIRECTION INPUT ;
    PORT
      LAYER met2 ;
        RECT 454.970 0.000 455.250 4.000 ;
    END
  END la_oen[88]
  PIN la_oen[89]
    DIRECTION INPUT ;
    PORT
      LAYER met2 ;
        RECT 458.650 0.000 458.930 4.000 ;
    END
  END la_oen[89]
  PIN la_oen[8]
    DIRECTION INPUT ;
    PORT
      LAYER met2 ;
        RECT 161.490 0.000 161.770 4.000 ;
    END
  END la_oen[8]
  PIN la_oen[90]
    DIRECTION INPUT ;
    PORT
      LAYER met2 ;
        RECT 462.330 0.000 462.610 4.000 ;
    END
  END la_oen[90]
  PIN la_oen[91]
    DIRECTION INPUT ;
    PORT
      LAYER met2 ;
        RECT 466.010 0.000 466.290 4.000 ;
    END
  END la_oen[91]
  PIN la_oen[92]
    DIRECTION INPUT ;
    PORT
      LAYER met2 ;
        RECT 469.690 0.000 469.970 4.000 ;
    END
  END la_oen[92]
  PIN la_oen[93]
    DIRECTION INPUT ;
    PORT
      LAYER met2 ;
        RECT 473.370 0.000 473.650 4.000 ;
    END
  END la_oen[93]
  PIN la_oen[94]
    DIRECTION INPUT ;
    PORT
      LAYER met2 ;
        RECT 477.050 0.000 477.330 4.000 ;
    END
  END la_oen[94]
  PIN la_oen[95]
    DIRECTION INPUT ;
    PORT
      LAYER met2 ;
        RECT 480.730 0.000 481.010 4.000 ;
    END
  END la_oen[95]
  PIN la_oen[96]
    DIRECTION INPUT ;
    PORT
      LAYER met2 ;
        RECT 484.410 0.000 484.690 4.000 ;
    END
  END la_oen[96]
  PIN la_oen[97]
    DIRECTION INPUT ;
    PORT
      LAYER met2 ;
        RECT 488.090 0.000 488.370 4.000 ;
    END
  END la_oen[97]
  PIN la_oen[98]
    DIRECTION INPUT ;
    PORT
      LAYER met2 ;
        RECT 491.770 0.000 492.050 4.000 ;
    END
  END la_oen[98]
  PIN la_oen[99]
    DIRECTION INPUT ;
    PORT
      LAYER met2 ;
        RECT 495.450 0.000 495.730 4.000 ;
    END
  END la_oen[99]
  PIN la_oen[9]
    DIRECTION INPUT ;
    PORT
      LAYER met2 ;
        RECT 165.170 0.000 165.450 4.000 ;
    END
  END la_oen[9]
  PIN wb_clk_i
    DIRECTION INPUT ;
    PORT
      LAYER met2 ;
        RECT 0.030 0.000 0.310 4.000 ;
    END
  END wb_clk_i
  PIN wb_rst_i
    DIRECTION INPUT ;
    PORT
      LAYER met2 ;
        RECT 0.950 0.000 1.230 4.000 ;
    END
  END wb_rst_i
  PIN wbs_ack_o
    DIRECTION OUTPUT TRISTATE ;
    PORT
      LAYER met2 ;
        RECT 2.330 0.000 2.610 4.000 ;
    END
  END wbs_ack_o
  PIN wbs_adr_i[0]
    DIRECTION INPUT ;
    PORT
      LAYER met2 ;
        RECT 6.930 0.000 7.210 4.000 ;
    END
  END wbs_adr_i[0]
  PIN wbs_adr_i[10]
    DIRECTION INPUT ;
    PORT
      LAYER met2 ;
        RECT 48.790 0.000 49.070 4.000 ;
    END
  END wbs_adr_i[10]
  PIN wbs_adr_i[11]
    DIRECTION INPUT ;
    PORT
      LAYER met2 ;
        RECT 52.470 0.000 52.750 4.000 ;
    END
  END wbs_adr_i[11]
  PIN wbs_adr_i[12]
    DIRECTION INPUT ;
    PORT
      LAYER met2 ;
        RECT 56.150 0.000 56.430 4.000 ;
    END
  END wbs_adr_i[12]
  PIN wbs_adr_i[13]
    DIRECTION INPUT ;
    PORT
      LAYER met2 ;
        RECT 59.830 0.000 60.110 4.000 ;
    END
  END wbs_adr_i[13]
  PIN wbs_adr_i[14]
    DIRECTION INPUT ;
    PORT
      LAYER met2 ;
        RECT 63.510 0.000 63.790 4.000 ;
    END
  END wbs_adr_i[14]
  PIN wbs_adr_i[15]
    DIRECTION INPUT ;
    PORT
      LAYER met2 ;
        RECT 67.190 0.000 67.470 4.000 ;
    END
  END wbs_adr_i[15]
  PIN wbs_adr_i[16]
    DIRECTION INPUT ;
    PORT
      LAYER met2 ;
        RECT 70.870 0.000 71.150 4.000 ;
    END
  END wbs_adr_i[16]
  PIN wbs_adr_i[17]
    DIRECTION INPUT ;
    PORT
      LAYER met2 ;
        RECT 74.550 0.000 74.830 4.000 ;
    END
  END wbs_adr_i[17]
  PIN wbs_adr_i[18]
    DIRECTION INPUT ;
    PORT
      LAYER met2 ;
        RECT 78.230 0.000 78.510 4.000 ;
    END
  END wbs_adr_i[18]
  PIN wbs_adr_i[19]
    DIRECTION INPUT ;
    PORT
      LAYER met2 ;
        RECT 81.910 0.000 82.190 4.000 ;
    END
  END wbs_adr_i[19]
  PIN wbs_adr_i[1]
    DIRECTION INPUT ;
    PORT
      LAYER met2 ;
        RECT 11.990 0.000 12.270 4.000 ;
    END
  END wbs_adr_i[1]
  PIN wbs_adr_i[20]
    DIRECTION INPUT ;
    PORT
      LAYER met2 ;
        RECT 85.590 0.000 85.870 4.000 ;
    END
  END wbs_adr_i[20]
  PIN wbs_adr_i[21]
    DIRECTION INPUT ;
    PORT
      LAYER met2 ;
        RECT 89.270 0.000 89.550 4.000 ;
    END
  END wbs_adr_i[21]
  PIN wbs_adr_i[22]
    DIRECTION INPUT ;
    PORT
      LAYER met2 ;
        RECT 92.950 0.000 93.230 4.000 ;
    END
  END wbs_adr_i[22]
  PIN wbs_adr_i[23]
    DIRECTION INPUT ;
    PORT
      LAYER met2 ;
        RECT 96.630 0.000 96.910 4.000 ;
    END
  END wbs_adr_i[23]
  PIN wbs_adr_i[24]
    DIRECTION INPUT ;
    PORT
      LAYER met2 ;
        RECT 100.310 0.000 100.590 4.000 ;
    END
  END wbs_adr_i[24]
  PIN wbs_adr_i[25]
    DIRECTION INPUT ;
    PORT
      LAYER met2 ;
        RECT 103.990 0.000 104.270 4.000 ;
    END
  END wbs_adr_i[25]
  PIN wbs_adr_i[26]
    DIRECTION INPUT ;
    PORT
      LAYER met2 ;
        RECT 107.670 0.000 107.950 4.000 ;
    END
  END wbs_adr_i[26]
  PIN wbs_adr_i[27]
    DIRECTION INPUT ;
    PORT
      LAYER met2 ;
        RECT 111.350 0.000 111.630 4.000 ;
    END
  END wbs_adr_i[27]
  PIN wbs_adr_i[28]
    DIRECTION INPUT ;
    PORT
      LAYER met2 ;
        RECT 115.030 0.000 115.310 4.000 ;
    END
  END wbs_adr_i[28]
  PIN wbs_adr_i[29]
    DIRECTION INPUT ;
    PORT
      LAYER met2 ;
        RECT 118.710 0.000 118.990 4.000 ;
    END
  END wbs_adr_i[29]
  PIN wbs_adr_i[2]
    DIRECTION INPUT ;
    PORT
      LAYER met2 ;
        RECT 17.050 0.000 17.330 4.000 ;
    END
  END wbs_adr_i[2]
  PIN wbs_adr_i[30]
    DIRECTION INPUT ;
    PORT
      LAYER met2 ;
        RECT 122.390 0.000 122.670 4.000 ;
    END
  END wbs_adr_i[30]
  PIN wbs_adr_i[31]
    DIRECTION INPUT ;
    PORT
      LAYER met2 ;
        RECT 126.070 0.000 126.350 4.000 ;
    END
  END wbs_adr_i[31]
  PIN wbs_adr_i[3]
    DIRECTION INPUT ;
    PORT
      LAYER met2 ;
        RECT 21.650 0.000 21.930 4.000 ;
    END
  END wbs_adr_i[3]
  PIN wbs_adr_i[4]
    DIRECTION INPUT ;
    PORT
      LAYER met2 ;
        RECT 26.710 0.000 26.990 4.000 ;
    END
  END wbs_adr_i[4]
  PIN wbs_adr_i[5]
    DIRECTION INPUT ;
    PORT
      LAYER met2 ;
        RECT 30.390 0.000 30.670 4.000 ;
    END
  END wbs_adr_i[5]
  PIN wbs_adr_i[6]
    DIRECTION INPUT ;
    PORT
      LAYER met2 ;
        RECT 34.070 0.000 34.350 4.000 ;
    END
  END wbs_adr_i[6]
  PIN wbs_adr_i[7]
    DIRECTION INPUT ;
    PORT
      LAYER met2 ;
        RECT 37.750 0.000 38.030 4.000 ;
    END
  END wbs_adr_i[7]
  PIN wbs_adr_i[8]
    DIRECTION INPUT ;
    PORT
      LAYER met2 ;
        RECT 41.430 0.000 41.710 4.000 ;
    END
  END wbs_adr_i[8]
  PIN wbs_adr_i[9]
    DIRECTION INPUT ;
    PORT
      LAYER met2 ;
        RECT 45.110 0.000 45.390 4.000 ;
    END
  END wbs_adr_i[9]
  PIN wbs_cyc_i
    DIRECTION INPUT ;
    PORT
      LAYER met2 ;
        RECT 3.250 0.000 3.530 4.000 ;
    END
  END wbs_cyc_i
  PIN wbs_dat_i[0]
    DIRECTION INPUT ;
    PORT
      LAYER met2 ;
        RECT 8.310 0.000 8.590 4.000 ;
    END
  END wbs_dat_i[0]
  PIN wbs_dat_i[10]
    DIRECTION INPUT ;
    PORT
      LAYER met2 ;
        RECT 50.170 0.000 50.450 4.000 ;
    END
  END wbs_dat_i[10]
  PIN wbs_dat_i[11]
    DIRECTION INPUT ;
    PORT
      LAYER met2 ;
        RECT 53.850 0.000 54.130 4.000 ;
    END
  END wbs_dat_i[11]
  PIN wbs_dat_i[12]
    DIRECTION INPUT ;
    PORT
      LAYER met2 ;
        RECT 57.530 0.000 57.810 4.000 ;
    END
  END wbs_dat_i[12]
  PIN wbs_dat_i[13]
    DIRECTION INPUT ;
    PORT
      LAYER met2 ;
        RECT 61.210 0.000 61.490 4.000 ;
    END
  END wbs_dat_i[13]
  PIN wbs_dat_i[14]
    DIRECTION INPUT ;
    PORT
      LAYER met2 ;
        RECT 64.890 0.000 65.170 4.000 ;
    END
  END wbs_dat_i[14]
  PIN wbs_dat_i[15]
    DIRECTION INPUT ;
    PORT
      LAYER met2 ;
        RECT 68.570 0.000 68.850 4.000 ;
    END
  END wbs_dat_i[15]
  PIN wbs_dat_i[16]
    DIRECTION INPUT ;
    PORT
      LAYER met2 ;
        RECT 72.250 0.000 72.530 4.000 ;
    END
  END wbs_dat_i[16]
  PIN wbs_dat_i[17]
    DIRECTION INPUT ;
    PORT
      LAYER met2 ;
        RECT 75.470 0.000 75.750 4.000 ;
    END
  END wbs_dat_i[17]
  PIN wbs_dat_i[18]
    DIRECTION INPUT ;
    PORT
      LAYER met2 ;
        RECT 79.150 0.000 79.430 4.000 ;
    END
  END wbs_dat_i[18]
  PIN wbs_dat_i[19]
    DIRECTION INPUT ;
    PORT
      LAYER met2 ;
        RECT 82.830 0.000 83.110 4.000 ;
    END
  END wbs_dat_i[19]
  PIN wbs_dat_i[1]
    DIRECTION INPUT ;
    PORT
      LAYER met2 ;
        RECT 13.370 0.000 13.650 4.000 ;
    END
  END wbs_dat_i[1]
  PIN wbs_dat_i[20]
    DIRECTION INPUT ;
    PORT
      LAYER met2 ;
        RECT 86.510 0.000 86.790 4.000 ;
    END
  END wbs_dat_i[20]
  PIN wbs_dat_i[21]
    DIRECTION INPUT ;
    PORT
      LAYER met2 ;
        RECT 90.190 0.000 90.470 4.000 ;
    END
  END wbs_dat_i[21]
  PIN wbs_dat_i[22]
    DIRECTION INPUT ;
    PORT
      LAYER met2 ;
        RECT 93.870 0.000 94.150 4.000 ;
    END
  END wbs_dat_i[22]
  PIN wbs_dat_i[23]
    DIRECTION INPUT ;
    PORT
      LAYER met2 ;
        RECT 97.550 0.000 97.830 4.000 ;
    END
  END wbs_dat_i[23]
  PIN wbs_dat_i[24]
    DIRECTION INPUT ;
    PORT
      LAYER met2 ;
        RECT 101.230 0.000 101.510 4.000 ;
    END
  END wbs_dat_i[24]
  PIN wbs_dat_i[25]
    DIRECTION INPUT ;
    PORT
      LAYER met2 ;
        RECT 104.910 0.000 105.190 4.000 ;
    END
  END wbs_dat_i[25]
  PIN wbs_dat_i[26]
    DIRECTION INPUT ;
    PORT
      LAYER met2 ;
        RECT 108.590 0.000 108.870 4.000 ;
    END
  END wbs_dat_i[26]
  PIN wbs_dat_i[27]
    DIRECTION INPUT ;
    PORT
      LAYER met2 ;
        RECT 112.270 0.000 112.550 4.000 ;
    END
  END wbs_dat_i[27]
  PIN wbs_dat_i[28]
    DIRECTION INPUT ;
    PORT
      LAYER met2 ;
        RECT 115.950 0.000 116.230 4.000 ;
    END
  END wbs_dat_i[28]
  PIN wbs_dat_i[29]
    DIRECTION INPUT ;
    PORT
      LAYER met2 ;
        RECT 119.630 0.000 119.910 4.000 ;
    END
  END wbs_dat_i[29]
  PIN wbs_dat_i[2]
    DIRECTION INPUT ;
    PORT
      LAYER met2 ;
        RECT 17.970 0.000 18.250 4.000 ;
    END
  END wbs_dat_i[2]
  PIN wbs_dat_i[30]
    DIRECTION INPUT ;
    PORT
      LAYER met2 ;
        RECT 123.310 0.000 123.590 4.000 ;
    END
  END wbs_dat_i[30]
  PIN wbs_dat_i[31]
    DIRECTION INPUT ;
    PORT
      LAYER met2 ;
        RECT 126.990 0.000 127.270 4.000 ;
    END
  END wbs_dat_i[31]
  PIN wbs_dat_i[3]
    DIRECTION INPUT ;
    PORT
      LAYER met2 ;
        RECT 23.030 0.000 23.310 4.000 ;
    END
  END wbs_dat_i[3]
  PIN wbs_dat_i[4]
    DIRECTION INPUT ;
    PORT
      LAYER met2 ;
        RECT 28.090 0.000 28.370 4.000 ;
    END
  END wbs_dat_i[4]
  PIN wbs_dat_i[5]
    DIRECTION INPUT ;
    PORT
      LAYER met2 ;
        RECT 31.770 0.000 32.050 4.000 ;
    END
  END wbs_dat_i[5]
  PIN wbs_dat_i[6]
    DIRECTION INPUT ;
    PORT
      LAYER met2 ;
        RECT 35.450 0.000 35.730 4.000 ;
    END
  END wbs_dat_i[6]
  PIN wbs_dat_i[7]
    DIRECTION INPUT ;
    PORT
      LAYER met2 ;
        RECT 39.130 0.000 39.410 4.000 ;
    END
  END wbs_dat_i[7]
  PIN wbs_dat_i[8]
    DIRECTION INPUT ;
    PORT
      LAYER met2 ;
        RECT 42.810 0.000 43.090 4.000 ;
    END
  END wbs_dat_i[8]
  PIN wbs_dat_i[9]
    DIRECTION INPUT ;
    PORT
      LAYER met2 ;
        RECT 46.490 0.000 46.770 4.000 ;
    END
  END wbs_dat_i[9]
  PIN wbs_dat_o[0]
    DIRECTION OUTPUT TRISTATE ;
    PORT
      LAYER met2 ;
        RECT 9.690 0.000 9.970 4.000 ;
    END
  END wbs_dat_o[0]
  PIN wbs_dat_o[10]
    DIRECTION OUTPUT TRISTATE ;
    PORT
      LAYER met2 ;
        RECT 51.090 0.000 51.370 4.000 ;
    END
  END wbs_dat_o[10]
  PIN wbs_dat_o[11]
    DIRECTION OUTPUT TRISTATE ;
    PORT
      LAYER met2 ;
        RECT 54.770 0.000 55.050 4.000 ;
    END
  END wbs_dat_o[11]
  PIN wbs_dat_o[12]
    DIRECTION OUTPUT TRISTATE ;
    PORT
      LAYER met2 ;
        RECT 58.450 0.000 58.730 4.000 ;
    END
  END wbs_dat_o[12]
  PIN wbs_dat_o[13]
    DIRECTION OUTPUT TRISTATE ;
    PORT
      LAYER met2 ;
        RECT 62.130 0.000 62.410 4.000 ;
    END
  END wbs_dat_o[13]
  PIN wbs_dat_o[14]
    DIRECTION OUTPUT TRISTATE ;
    PORT
      LAYER met2 ;
        RECT 65.810 0.000 66.090 4.000 ;
    END
  END wbs_dat_o[14]
  PIN wbs_dat_o[15]
    DIRECTION OUTPUT TRISTATE ;
    PORT
      LAYER met2 ;
        RECT 69.490 0.000 69.770 4.000 ;
    END
  END wbs_dat_o[15]
  PIN wbs_dat_o[16]
    DIRECTION OUTPUT TRISTATE ;
    PORT
      LAYER met2 ;
        RECT 73.170 0.000 73.450 4.000 ;
    END
  END wbs_dat_o[16]
  PIN wbs_dat_o[17]
    DIRECTION OUTPUT TRISTATE ;
    PORT
      LAYER met2 ;
        RECT 76.850 0.000 77.130 4.000 ;
    END
  END wbs_dat_o[17]
  PIN wbs_dat_o[18]
    DIRECTION OUTPUT TRISTATE ;
    PORT
      LAYER met2 ;
        RECT 80.530 0.000 80.810 4.000 ;
    END
  END wbs_dat_o[18]
  PIN wbs_dat_o[19]
    DIRECTION OUTPUT TRISTATE ;
    PORT
      LAYER met2 ;
        RECT 84.210 0.000 84.490 4.000 ;
    END
  END wbs_dat_o[19]
  PIN wbs_dat_o[1]
    DIRECTION OUTPUT TRISTATE ;
    PORT
      LAYER met2 ;
        RECT 14.290 0.000 14.570 4.000 ;
    END
  END wbs_dat_o[1]
  PIN wbs_dat_o[20]
    DIRECTION OUTPUT TRISTATE ;
    PORT
      LAYER met2 ;
        RECT 87.890 0.000 88.170 4.000 ;
    END
  END wbs_dat_o[20]
  PIN wbs_dat_o[21]
    DIRECTION OUTPUT TRISTATE ;
    PORT
      LAYER met2 ;
        RECT 91.570 0.000 91.850 4.000 ;
    END
  END wbs_dat_o[21]
  PIN wbs_dat_o[22]
    DIRECTION OUTPUT TRISTATE ;
    PORT
      LAYER met2 ;
        RECT 95.250 0.000 95.530 4.000 ;
    END
  END wbs_dat_o[22]
  PIN wbs_dat_o[23]
    DIRECTION OUTPUT TRISTATE ;
    PORT
      LAYER met2 ;
        RECT 98.930 0.000 99.210 4.000 ;
    END
  END wbs_dat_o[23]
  PIN wbs_dat_o[24]
    DIRECTION OUTPUT TRISTATE ;
    PORT
      LAYER met2 ;
        RECT 102.610 0.000 102.890 4.000 ;
    END
  END wbs_dat_o[24]
  PIN wbs_dat_o[25]
    DIRECTION OUTPUT TRISTATE ;
    PORT
      LAYER met2 ;
        RECT 106.290 0.000 106.570 4.000 ;
    END
  END wbs_dat_o[25]
  PIN wbs_dat_o[26]
    DIRECTION OUTPUT TRISTATE ;
    PORT
      LAYER met2 ;
        RECT 109.970 0.000 110.250 4.000 ;
    END
  END wbs_dat_o[26]
  PIN wbs_dat_o[27]
    DIRECTION OUTPUT TRISTATE ;
    PORT
      LAYER met2 ;
        RECT 113.650 0.000 113.930 4.000 ;
    END
  END wbs_dat_o[27]
  PIN wbs_dat_o[28]
    DIRECTION OUTPUT TRISTATE ;
    PORT
      LAYER met2 ;
        RECT 117.330 0.000 117.610 4.000 ;
    END
  END wbs_dat_o[28]
  PIN wbs_dat_o[29]
    DIRECTION OUTPUT TRISTATE ;
    PORT
      LAYER met2 ;
        RECT 121.010 0.000 121.290 4.000 ;
    END
  END wbs_dat_o[29]
  PIN wbs_dat_o[2]
    DIRECTION OUTPUT TRISTATE ;
    PORT
      LAYER met2 ;
        RECT 19.350 0.000 19.630 4.000 ;
    END
  END wbs_dat_o[2]
  PIN wbs_dat_o[30]
    DIRECTION OUTPUT TRISTATE ;
    PORT
      LAYER met2 ;
        RECT 124.690 0.000 124.970 4.000 ;
    END
  END wbs_dat_o[30]
  PIN wbs_dat_o[31]
    DIRECTION OUTPUT TRISTATE ;
    PORT
      LAYER met2 ;
        RECT 128.370 0.000 128.650 4.000 ;
    END
  END wbs_dat_o[31]
  PIN wbs_dat_o[3]
    DIRECTION OUTPUT TRISTATE ;
    PORT
      LAYER met2 ;
        RECT 24.410 0.000 24.690 4.000 ;
    END
  END wbs_dat_o[3]
  PIN wbs_dat_o[4]
    DIRECTION OUTPUT TRISTATE ;
    PORT
      LAYER met2 ;
        RECT 29.010 0.000 29.290 4.000 ;
    END
  END wbs_dat_o[4]
  PIN wbs_dat_o[5]
    DIRECTION OUTPUT TRISTATE ;
    PORT
      LAYER met2 ;
        RECT 32.690 0.000 32.970 4.000 ;
    END
  END wbs_dat_o[5]
  PIN wbs_dat_o[6]
    DIRECTION OUTPUT TRISTATE ;
    PORT
      LAYER met2 ;
        RECT 36.370 0.000 36.650 4.000 ;
    END
  END wbs_dat_o[6]
  PIN wbs_dat_o[7]
    DIRECTION OUTPUT TRISTATE ;
    PORT
      LAYER met2 ;
        RECT 40.050 0.000 40.330 4.000 ;
    END
  END wbs_dat_o[7]
  PIN wbs_dat_o[8]
    DIRECTION OUTPUT TRISTATE ;
    PORT
      LAYER met2 ;
        RECT 43.730 0.000 44.010 4.000 ;
    END
  END wbs_dat_o[8]
  PIN wbs_dat_o[9]
    DIRECTION OUTPUT TRISTATE ;
    PORT
      LAYER met2 ;
        RECT 47.410 0.000 47.690 4.000 ;
    END
  END wbs_dat_o[9]
  PIN wbs_sel_i[0]
    DIRECTION INPUT ;
    PORT
      LAYER met2 ;
        RECT 10.610 0.000 10.890 4.000 ;
    END
  END wbs_sel_i[0]
  PIN wbs_sel_i[1]
    DIRECTION INPUT ;
    PORT
      LAYER met2 ;
        RECT 15.670 0.000 15.950 4.000 ;
    END
  END wbs_sel_i[1]
  PIN wbs_sel_i[2]
    DIRECTION INPUT ;
    PORT
      LAYER met2 ;
        RECT 20.730 0.000 21.010 4.000 ;
    END
  END wbs_sel_i[2]
  PIN wbs_sel_i[3]
    DIRECTION INPUT ;
    PORT
      LAYER met2 ;
        RECT 25.330 0.000 25.610 4.000 ;
    END
  END wbs_sel_i[3]
  PIN wbs_stb_i
    DIRECTION INPUT ;
    PORT
      LAYER met2 ;
        RECT 4.630 0.000 4.910 4.000 ;
    END
  END wbs_stb_i
  PIN wbs_we_i
    DIRECTION INPUT ;
    PORT
      LAYER met2 ;
        RECT 6.010 0.000 6.290 4.000 ;
    END
  END wbs_we_i
  PIN VPWR
    DIRECTION INPUT ;
    USE POWER ;
    PORT
      LAYER met4 ;
        RECT 20.520 10.640 22.120 587.760 ;
    END
  END VPWR
  PIN VGND
    DIRECTION INPUT ;
    USE GROUND ;
    PORT
      LAYER met4 ;
        RECT 97.320 10.640 98.920 587.760 ;
    END
  END VGND
  OBS
      LAYER li1 ;
        RECT 5.000 8.245 593.800 587.605 ;
      LAYER met1 ;
        RECT 3.230 5.480 597.410 595.640 ;
      LAYER met2 ;
        RECT 0.030 595.720 1.590 596.000 ;
        RECT 2.430 595.720 6.650 596.000 ;
        RECT 7.490 595.720 11.710 596.000 ;
        RECT 12.550 595.720 17.230 596.000 ;
        RECT 18.070 595.720 22.290 596.000 ;
        RECT 23.130 595.720 27.810 596.000 ;
        RECT 28.650 595.720 32.870 596.000 ;
        RECT 33.710 595.720 38.390 596.000 ;
        RECT 39.230 595.720 43.450 596.000 ;
        RECT 44.290 595.720 48.510 596.000 ;
        RECT 49.350 595.720 54.030 596.000 ;
        RECT 54.870 595.720 59.090 596.000 ;
        RECT 59.930 595.720 64.610 596.000 ;
        RECT 65.450 595.720 69.670 596.000 ;
        RECT 70.510 595.720 75.190 596.000 ;
        RECT 76.030 595.720 80.250 596.000 ;
        RECT 81.090 595.720 85.770 596.000 ;
        RECT 86.610 595.720 90.830 596.000 ;
        RECT 91.670 595.720 95.890 596.000 ;
        RECT 96.730 595.720 101.410 596.000 ;
        RECT 102.250 595.720 106.470 596.000 ;
        RECT 107.310 595.720 111.990 596.000 ;
        RECT 112.830 595.720 117.050 596.000 ;
        RECT 117.890 595.720 122.570 596.000 ;
        RECT 123.410 595.720 127.630 596.000 ;
        RECT 128.470 595.720 132.690 596.000 ;
        RECT 133.530 595.720 138.210 596.000 ;
        RECT 139.050 595.720 143.270 596.000 ;
        RECT 144.110 595.720 148.790 596.000 ;
        RECT 149.630 595.720 153.850 596.000 ;
        RECT 154.690 595.720 159.370 596.000 ;
        RECT 160.210 595.720 164.430 596.000 ;
        RECT 165.270 595.720 169.950 596.000 ;
        RECT 170.790 595.720 175.010 596.000 ;
        RECT 175.850 595.720 180.070 596.000 ;
        RECT 180.910 595.720 185.590 596.000 ;
        RECT 186.430 595.720 190.650 596.000 ;
        RECT 191.490 595.720 196.170 596.000 ;
        RECT 197.010 595.720 201.230 596.000 ;
        RECT 202.070 595.720 206.750 596.000 ;
        RECT 207.590 595.720 211.810 596.000 ;
        RECT 212.650 595.720 216.870 596.000 ;
        RECT 217.710 595.720 222.390 596.000 ;
        RECT 223.230 595.720 227.450 596.000 ;
        RECT 228.290 595.720 232.970 596.000 ;
        RECT 233.810 595.720 238.030 596.000 ;
        RECT 238.870 595.720 243.550 596.000 ;
        RECT 244.390 595.720 248.610 596.000 ;
        RECT 249.450 595.720 254.130 596.000 ;
        RECT 254.970 595.720 259.190 596.000 ;
        RECT 260.030 595.720 264.250 596.000 ;
        RECT 265.090 595.720 269.770 596.000 ;
        RECT 270.610 595.720 274.830 596.000 ;
        RECT 275.670 595.720 280.350 596.000 ;
        RECT 281.190 595.720 285.410 596.000 ;
        RECT 286.250 595.720 290.930 596.000 ;
        RECT 291.770 595.720 295.990 596.000 ;
        RECT 296.830 595.720 301.510 596.000 ;
        RECT 302.350 595.720 306.570 596.000 ;
        RECT 307.410 595.720 311.630 596.000 ;
        RECT 312.470 595.720 317.150 596.000 ;
        RECT 317.990 595.720 322.210 596.000 ;
        RECT 323.050 595.720 327.730 596.000 ;
        RECT 328.570 595.720 332.790 596.000 ;
        RECT 333.630 595.720 338.310 596.000 ;
        RECT 339.150 595.720 343.370 596.000 ;
        RECT 344.210 595.720 348.430 596.000 ;
        RECT 349.270 595.720 353.950 596.000 ;
        RECT 354.790 595.720 359.010 596.000 ;
        RECT 359.850 595.720 364.530 596.000 ;
        RECT 365.370 595.720 369.590 596.000 ;
        RECT 370.430 595.720 375.110 596.000 ;
        RECT 375.950 595.720 380.170 596.000 ;
        RECT 381.010 595.720 385.690 596.000 ;
        RECT 386.530 595.720 390.750 596.000 ;
        RECT 391.590 595.720 395.810 596.000 ;
        RECT 396.650 595.720 401.330 596.000 ;
        RECT 402.170 595.720 406.390 596.000 ;
        RECT 407.230 595.720 411.910 596.000 ;
        RECT 412.750 595.720 416.970 596.000 ;
        RECT 417.810 595.720 422.490 596.000 ;
        RECT 423.330 595.720 427.550 596.000 ;
        RECT 428.390 595.720 432.610 596.000 ;
        RECT 433.450 595.720 438.130 596.000 ;
        RECT 438.970 595.720 443.190 596.000 ;
        RECT 444.030 595.720 448.710 596.000 ;
        RECT 449.550 595.720 453.770 596.000 ;
        RECT 454.610 595.720 459.290 596.000 ;
        RECT 460.130 595.720 464.350 596.000 ;
        RECT 465.190 595.720 469.870 596.000 ;
        RECT 470.710 595.720 474.930 596.000 ;
        RECT 475.770 595.720 479.990 596.000 ;
        RECT 480.830 595.720 485.510 596.000 ;
        RECT 486.350 595.720 490.570 596.000 ;
        RECT 491.410 595.720 496.090 596.000 ;
        RECT 496.930 595.720 501.150 596.000 ;
        RECT 501.990 595.720 506.670 596.000 ;
        RECT 507.510 595.720 511.730 596.000 ;
        RECT 512.570 595.720 516.790 596.000 ;
        RECT 517.630 595.720 522.310 596.000 ;
        RECT 523.150 595.720 527.370 596.000 ;
        RECT 528.210 595.720 532.890 596.000 ;
        RECT 533.730 595.720 537.950 596.000 ;
        RECT 538.790 595.720 543.470 596.000 ;
        RECT 544.310 595.720 548.530 596.000 ;
        RECT 549.370 595.720 554.050 596.000 ;
        RECT 554.890 595.720 559.110 596.000 ;
        RECT 559.950 595.720 564.170 596.000 ;
        RECT 565.010 595.720 569.690 596.000 ;
        RECT 570.530 595.720 574.750 596.000 ;
        RECT 575.590 595.720 580.270 596.000 ;
        RECT 581.110 595.720 585.330 596.000 ;
        RECT 586.170 595.720 590.850 596.000 ;
        RECT 591.690 595.720 595.910 596.000 ;
        RECT 596.750 595.720 597.380 596.000 ;
        RECT 0.030 4.280 597.380 595.720 ;
        RECT 0.590 4.000 0.670 4.280 ;
        RECT 1.510 4.000 2.050 4.280 ;
        RECT 2.890 4.000 2.970 4.280 ;
        RECT 3.810 4.000 4.350 4.280 ;
        RECT 5.190 4.000 5.730 4.280 ;
        RECT 6.570 4.000 6.650 4.280 ;
        RECT 7.490 4.000 8.030 4.280 ;
        RECT 8.870 4.000 9.410 4.280 ;
        RECT 10.250 4.000 10.330 4.280 ;
        RECT 11.170 4.000 11.710 4.280 ;
        RECT 12.550 4.000 13.090 4.280 ;
        RECT 13.930 4.000 14.010 4.280 ;
        RECT 14.850 4.000 15.390 4.280 ;
        RECT 16.230 4.000 16.770 4.280 ;
        RECT 17.610 4.000 17.690 4.280 ;
        RECT 18.530 4.000 19.070 4.280 ;
        RECT 19.910 4.000 20.450 4.280 ;
        RECT 21.290 4.000 21.370 4.280 ;
        RECT 22.210 4.000 22.750 4.280 ;
        RECT 23.590 4.000 24.130 4.280 ;
        RECT 24.970 4.000 25.050 4.280 ;
        RECT 25.890 4.000 26.430 4.280 ;
        RECT 27.270 4.000 27.810 4.280 ;
        RECT 28.650 4.000 28.730 4.280 ;
        RECT 29.570 4.000 30.110 4.280 ;
        RECT 30.950 4.000 31.490 4.280 ;
        RECT 32.330 4.000 32.410 4.280 ;
        RECT 33.250 4.000 33.790 4.280 ;
        RECT 34.630 4.000 35.170 4.280 ;
        RECT 36.010 4.000 36.090 4.280 ;
        RECT 36.930 4.000 37.470 4.280 ;
        RECT 38.310 4.000 38.850 4.280 ;
        RECT 39.690 4.000 39.770 4.280 ;
        RECT 40.610 4.000 41.150 4.280 ;
        RECT 41.990 4.000 42.530 4.280 ;
        RECT 43.370 4.000 43.450 4.280 ;
        RECT 44.290 4.000 44.830 4.280 ;
        RECT 45.670 4.000 46.210 4.280 ;
        RECT 47.050 4.000 47.130 4.280 ;
        RECT 47.970 4.000 48.510 4.280 ;
        RECT 49.350 4.000 49.890 4.280 ;
        RECT 50.730 4.000 50.810 4.280 ;
        RECT 51.650 4.000 52.190 4.280 ;
        RECT 53.030 4.000 53.570 4.280 ;
        RECT 54.410 4.000 54.490 4.280 ;
        RECT 55.330 4.000 55.870 4.280 ;
        RECT 56.710 4.000 57.250 4.280 ;
        RECT 58.090 4.000 58.170 4.280 ;
        RECT 59.010 4.000 59.550 4.280 ;
        RECT 60.390 4.000 60.930 4.280 ;
        RECT 61.770 4.000 61.850 4.280 ;
        RECT 62.690 4.000 63.230 4.280 ;
        RECT 64.070 4.000 64.610 4.280 ;
        RECT 65.450 4.000 65.530 4.280 ;
        RECT 66.370 4.000 66.910 4.280 ;
        RECT 67.750 4.000 68.290 4.280 ;
        RECT 69.130 4.000 69.210 4.280 ;
        RECT 70.050 4.000 70.590 4.280 ;
        RECT 71.430 4.000 71.970 4.280 ;
        RECT 72.810 4.000 72.890 4.280 ;
        RECT 73.730 4.000 74.270 4.280 ;
        RECT 75.110 4.000 75.190 4.280 ;
        RECT 76.030 4.000 76.570 4.280 ;
        RECT 77.410 4.000 77.950 4.280 ;
        RECT 78.790 4.000 78.870 4.280 ;
        RECT 79.710 4.000 80.250 4.280 ;
        RECT 81.090 4.000 81.630 4.280 ;
        RECT 82.470 4.000 82.550 4.280 ;
        RECT 83.390 4.000 83.930 4.280 ;
        RECT 84.770 4.000 85.310 4.280 ;
        RECT 86.150 4.000 86.230 4.280 ;
        RECT 87.070 4.000 87.610 4.280 ;
        RECT 88.450 4.000 88.990 4.280 ;
        RECT 89.830 4.000 89.910 4.280 ;
        RECT 90.750 4.000 91.290 4.280 ;
        RECT 92.130 4.000 92.670 4.280 ;
        RECT 93.510 4.000 93.590 4.280 ;
        RECT 94.430 4.000 94.970 4.280 ;
        RECT 95.810 4.000 96.350 4.280 ;
        RECT 97.190 4.000 97.270 4.280 ;
        RECT 98.110 4.000 98.650 4.280 ;
        RECT 99.490 4.000 100.030 4.280 ;
        RECT 100.870 4.000 100.950 4.280 ;
        RECT 101.790 4.000 102.330 4.280 ;
        RECT 103.170 4.000 103.710 4.280 ;
        RECT 104.550 4.000 104.630 4.280 ;
        RECT 105.470 4.000 106.010 4.280 ;
        RECT 106.850 4.000 107.390 4.280 ;
        RECT 108.230 4.000 108.310 4.280 ;
        RECT 109.150 4.000 109.690 4.280 ;
        RECT 110.530 4.000 111.070 4.280 ;
        RECT 111.910 4.000 111.990 4.280 ;
        RECT 112.830 4.000 113.370 4.280 ;
        RECT 114.210 4.000 114.750 4.280 ;
        RECT 115.590 4.000 115.670 4.280 ;
        RECT 116.510 4.000 117.050 4.280 ;
        RECT 117.890 4.000 118.430 4.280 ;
        RECT 119.270 4.000 119.350 4.280 ;
        RECT 120.190 4.000 120.730 4.280 ;
        RECT 121.570 4.000 122.110 4.280 ;
        RECT 122.950 4.000 123.030 4.280 ;
        RECT 123.870 4.000 124.410 4.280 ;
        RECT 125.250 4.000 125.790 4.280 ;
        RECT 126.630 4.000 126.710 4.280 ;
        RECT 127.550 4.000 128.090 4.280 ;
        RECT 128.930 4.000 129.470 4.280 ;
        RECT 130.310 4.000 130.390 4.280 ;
        RECT 131.230 4.000 131.770 4.280 ;
        RECT 132.610 4.000 133.150 4.280 ;
        RECT 133.990 4.000 134.070 4.280 ;
        RECT 134.910 4.000 135.450 4.280 ;
        RECT 136.290 4.000 136.830 4.280 ;
        RECT 137.670 4.000 137.750 4.280 ;
        RECT 138.590 4.000 139.130 4.280 ;
        RECT 139.970 4.000 140.510 4.280 ;
        RECT 141.350 4.000 141.430 4.280 ;
        RECT 142.270 4.000 142.810 4.280 ;
        RECT 143.650 4.000 144.190 4.280 ;
        RECT 145.030 4.000 145.110 4.280 ;
        RECT 145.950 4.000 146.490 4.280 ;
        RECT 147.330 4.000 147.870 4.280 ;
        RECT 148.710 4.000 148.790 4.280 ;
        RECT 149.630 4.000 150.170 4.280 ;
        RECT 151.010 4.000 151.090 4.280 ;
        RECT 151.930 4.000 152.470 4.280 ;
        RECT 153.310 4.000 153.850 4.280 ;
        RECT 154.690 4.000 154.770 4.280 ;
        RECT 155.610 4.000 156.150 4.280 ;
        RECT 156.990 4.000 157.530 4.280 ;
        RECT 158.370 4.000 158.450 4.280 ;
        RECT 159.290 4.000 159.830 4.280 ;
        RECT 160.670 4.000 161.210 4.280 ;
        RECT 162.050 4.000 162.130 4.280 ;
        RECT 162.970 4.000 163.510 4.280 ;
        RECT 164.350 4.000 164.890 4.280 ;
        RECT 165.730 4.000 165.810 4.280 ;
        RECT 166.650 4.000 167.190 4.280 ;
        RECT 168.030 4.000 168.570 4.280 ;
        RECT 169.410 4.000 169.490 4.280 ;
        RECT 170.330 4.000 170.870 4.280 ;
        RECT 171.710 4.000 172.250 4.280 ;
        RECT 173.090 4.000 173.170 4.280 ;
        RECT 174.010 4.000 174.550 4.280 ;
        RECT 175.390 4.000 175.930 4.280 ;
        RECT 176.770 4.000 176.850 4.280 ;
        RECT 177.690 4.000 178.230 4.280 ;
        RECT 179.070 4.000 179.610 4.280 ;
        RECT 180.450 4.000 180.530 4.280 ;
        RECT 181.370 4.000 181.910 4.280 ;
        RECT 182.750 4.000 183.290 4.280 ;
        RECT 184.130 4.000 184.210 4.280 ;
        RECT 185.050 4.000 185.590 4.280 ;
        RECT 186.430 4.000 186.970 4.280 ;
        RECT 187.810 4.000 187.890 4.280 ;
        RECT 188.730 4.000 189.270 4.280 ;
        RECT 190.110 4.000 190.650 4.280 ;
        RECT 191.490 4.000 191.570 4.280 ;
        RECT 192.410 4.000 192.950 4.280 ;
        RECT 193.790 4.000 194.330 4.280 ;
        RECT 195.170 4.000 195.250 4.280 ;
        RECT 196.090 4.000 196.630 4.280 ;
        RECT 197.470 4.000 198.010 4.280 ;
        RECT 198.850 4.000 198.930 4.280 ;
        RECT 199.770 4.000 200.310 4.280 ;
        RECT 201.150 4.000 201.690 4.280 ;
        RECT 202.530 4.000 202.610 4.280 ;
        RECT 203.450 4.000 203.990 4.280 ;
        RECT 204.830 4.000 205.370 4.280 ;
        RECT 206.210 4.000 206.290 4.280 ;
        RECT 207.130 4.000 207.670 4.280 ;
        RECT 208.510 4.000 209.050 4.280 ;
        RECT 209.890 4.000 209.970 4.280 ;
        RECT 210.810 4.000 211.350 4.280 ;
        RECT 212.190 4.000 212.730 4.280 ;
        RECT 213.570 4.000 213.650 4.280 ;
        RECT 214.490 4.000 215.030 4.280 ;
        RECT 215.870 4.000 216.410 4.280 ;
        RECT 217.250 4.000 217.330 4.280 ;
        RECT 218.170 4.000 218.710 4.280 ;
        RECT 219.550 4.000 220.090 4.280 ;
        RECT 220.930 4.000 221.010 4.280 ;
        RECT 221.850 4.000 222.390 4.280 ;
        RECT 223.230 4.000 223.770 4.280 ;
        RECT 224.610 4.000 224.690 4.280 ;
        RECT 225.530 4.000 226.070 4.280 ;
        RECT 226.910 4.000 226.990 4.280 ;
        RECT 227.830 4.000 228.370 4.280 ;
        RECT 229.210 4.000 229.750 4.280 ;
        RECT 230.590 4.000 230.670 4.280 ;
        RECT 231.510 4.000 232.050 4.280 ;
        RECT 232.890 4.000 233.430 4.280 ;
        RECT 234.270 4.000 234.350 4.280 ;
        RECT 235.190 4.000 235.730 4.280 ;
        RECT 236.570 4.000 237.110 4.280 ;
        RECT 237.950 4.000 238.030 4.280 ;
        RECT 238.870 4.000 239.410 4.280 ;
        RECT 240.250 4.000 240.790 4.280 ;
        RECT 241.630 4.000 241.710 4.280 ;
        RECT 242.550 4.000 243.090 4.280 ;
        RECT 243.930 4.000 244.470 4.280 ;
        RECT 245.310 4.000 245.390 4.280 ;
        RECT 246.230 4.000 246.770 4.280 ;
        RECT 247.610 4.000 248.150 4.280 ;
        RECT 248.990 4.000 249.070 4.280 ;
        RECT 249.910 4.000 250.450 4.280 ;
        RECT 251.290 4.000 251.830 4.280 ;
        RECT 252.670 4.000 252.750 4.280 ;
        RECT 253.590 4.000 254.130 4.280 ;
        RECT 254.970 4.000 255.510 4.280 ;
        RECT 256.350 4.000 256.430 4.280 ;
        RECT 257.270 4.000 257.810 4.280 ;
        RECT 258.650 4.000 259.190 4.280 ;
        RECT 260.030 4.000 260.110 4.280 ;
        RECT 260.950 4.000 261.490 4.280 ;
        RECT 262.330 4.000 262.870 4.280 ;
        RECT 263.710 4.000 263.790 4.280 ;
        RECT 264.630 4.000 265.170 4.280 ;
        RECT 266.010 4.000 266.550 4.280 ;
        RECT 267.390 4.000 267.470 4.280 ;
        RECT 268.310 4.000 268.850 4.280 ;
        RECT 269.690 4.000 270.230 4.280 ;
        RECT 271.070 4.000 271.150 4.280 ;
        RECT 271.990 4.000 272.530 4.280 ;
        RECT 273.370 4.000 273.910 4.280 ;
        RECT 274.750 4.000 274.830 4.280 ;
        RECT 275.670 4.000 276.210 4.280 ;
        RECT 277.050 4.000 277.590 4.280 ;
        RECT 278.430 4.000 278.510 4.280 ;
        RECT 279.350 4.000 279.890 4.280 ;
        RECT 280.730 4.000 281.270 4.280 ;
        RECT 282.110 4.000 282.190 4.280 ;
        RECT 283.030 4.000 283.570 4.280 ;
        RECT 284.410 4.000 284.950 4.280 ;
        RECT 285.790 4.000 285.870 4.280 ;
        RECT 286.710 4.000 287.250 4.280 ;
        RECT 288.090 4.000 288.630 4.280 ;
        RECT 289.470 4.000 289.550 4.280 ;
        RECT 290.390 4.000 290.930 4.280 ;
        RECT 291.770 4.000 292.310 4.280 ;
        RECT 293.150 4.000 293.230 4.280 ;
        RECT 294.070 4.000 294.610 4.280 ;
        RECT 295.450 4.000 295.990 4.280 ;
        RECT 296.830 4.000 296.910 4.280 ;
        RECT 297.750 4.000 298.290 4.280 ;
        RECT 299.130 4.000 299.670 4.280 ;
        RECT 300.510 4.000 300.590 4.280 ;
        RECT 301.430 4.000 301.970 4.280 ;
        RECT 302.810 4.000 302.890 4.280 ;
        RECT 303.730 4.000 304.270 4.280 ;
        RECT 305.110 4.000 305.650 4.280 ;
        RECT 306.490 4.000 306.570 4.280 ;
        RECT 307.410 4.000 307.950 4.280 ;
        RECT 308.790 4.000 309.330 4.280 ;
        RECT 310.170 4.000 310.250 4.280 ;
        RECT 311.090 4.000 311.630 4.280 ;
        RECT 312.470 4.000 313.010 4.280 ;
        RECT 313.850 4.000 313.930 4.280 ;
        RECT 314.770 4.000 315.310 4.280 ;
        RECT 316.150 4.000 316.690 4.280 ;
        RECT 317.530 4.000 317.610 4.280 ;
        RECT 318.450 4.000 318.990 4.280 ;
        RECT 319.830 4.000 320.370 4.280 ;
        RECT 321.210 4.000 321.290 4.280 ;
        RECT 322.130 4.000 322.670 4.280 ;
        RECT 323.510 4.000 324.050 4.280 ;
        RECT 324.890 4.000 324.970 4.280 ;
        RECT 325.810 4.000 326.350 4.280 ;
        RECT 327.190 4.000 327.730 4.280 ;
        RECT 328.570 4.000 328.650 4.280 ;
        RECT 329.490 4.000 330.030 4.280 ;
        RECT 330.870 4.000 331.410 4.280 ;
        RECT 332.250 4.000 332.330 4.280 ;
        RECT 333.170 4.000 333.710 4.280 ;
        RECT 334.550 4.000 335.090 4.280 ;
        RECT 335.930 4.000 336.010 4.280 ;
        RECT 336.850 4.000 337.390 4.280 ;
        RECT 338.230 4.000 338.770 4.280 ;
        RECT 339.610 4.000 339.690 4.280 ;
        RECT 340.530 4.000 341.070 4.280 ;
        RECT 341.910 4.000 342.450 4.280 ;
        RECT 343.290 4.000 343.370 4.280 ;
        RECT 344.210 4.000 344.750 4.280 ;
        RECT 345.590 4.000 346.130 4.280 ;
        RECT 346.970 4.000 347.050 4.280 ;
        RECT 347.890 4.000 348.430 4.280 ;
        RECT 349.270 4.000 349.810 4.280 ;
        RECT 350.650 4.000 350.730 4.280 ;
        RECT 351.570 4.000 352.110 4.280 ;
        RECT 352.950 4.000 353.490 4.280 ;
        RECT 354.330 4.000 354.410 4.280 ;
        RECT 355.250 4.000 355.790 4.280 ;
        RECT 356.630 4.000 357.170 4.280 ;
        RECT 358.010 4.000 358.090 4.280 ;
        RECT 358.930 4.000 359.470 4.280 ;
        RECT 360.310 4.000 360.850 4.280 ;
        RECT 361.690 4.000 361.770 4.280 ;
        RECT 362.610 4.000 363.150 4.280 ;
        RECT 363.990 4.000 364.530 4.280 ;
        RECT 365.370 4.000 365.450 4.280 ;
        RECT 366.290 4.000 366.830 4.280 ;
        RECT 367.670 4.000 368.210 4.280 ;
        RECT 369.050 4.000 369.130 4.280 ;
        RECT 369.970 4.000 370.510 4.280 ;
        RECT 371.350 4.000 371.890 4.280 ;
        RECT 372.730 4.000 372.810 4.280 ;
        RECT 373.650 4.000 374.190 4.280 ;
        RECT 375.030 4.000 375.110 4.280 ;
        RECT 375.950 4.000 376.490 4.280 ;
        RECT 377.330 4.000 377.870 4.280 ;
        RECT 378.710 4.000 378.790 4.280 ;
        RECT 379.630 4.000 380.170 4.280 ;
        RECT 381.010 4.000 381.550 4.280 ;
        RECT 382.390 4.000 382.470 4.280 ;
        RECT 383.310 4.000 383.850 4.280 ;
        RECT 384.690 4.000 385.230 4.280 ;
        RECT 386.070 4.000 386.150 4.280 ;
        RECT 386.990 4.000 387.530 4.280 ;
        RECT 388.370 4.000 388.910 4.280 ;
        RECT 389.750 4.000 389.830 4.280 ;
        RECT 390.670 4.000 391.210 4.280 ;
        RECT 392.050 4.000 392.590 4.280 ;
        RECT 393.430 4.000 393.510 4.280 ;
        RECT 394.350 4.000 394.890 4.280 ;
        RECT 395.730 4.000 396.270 4.280 ;
        RECT 397.110 4.000 397.190 4.280 ;
        RECT 398.030 4.000 398.570 4.280 ;
        RECT 399.410 4.000 399.950 4.280 ;
        RECT 400.790 4.000 400.870 4.280 ;
        RECT 401.710 4.000 402.250 4.280 ;
        RECT 403.090 4.000 403.630 4.280 ;
        RECT 404.470 4.000 404.550 4.280 ;
        RECT 405.390 4.000 405.930 4.280 ;
        RECT 406.770 4.000 407.310 4.280 ;
        RECT 408.150 4.000 408.230 4.280 ;
        RECT 409.070 4.000 409.610 4.280 ;
        RECT 410.450 4.000 410.990 4.280 ;
        RECT 411.830 4.000 411.910 4.280 ;
        RECT 412.750 4.000 413.290 4.280 ;
        RECT 414.130 4.000 414.670 4.280 ;
        RECT 415.510 4.000 415.590 4.280 ;
        RECT 416.430 4.000 416.970 4.280 ;
        RECT 417.810 4.000 418.350 4.280 ;
        RECT 419.190 4.000 419.270 4.280 ;
        RECT 420.110 4.000 420.650 4.280 ;
        RECT 421.490 4.000 422.030 4.280 ;
        RECT 422.870 4.000 422.950 4.280 ;
        RECT 423.790 4.000 424.330 4.280 ;
        RECT 425.170 4.000 425.710 4.280 ;
        RECT 426.550 4.000 426.630 4.280 ;
        RECT 427.470 4.000 428.010 4.280 ;
        RECT 428.850 4.000 429.390 4.280 ;
        RECT 430.230 4.000 430.310 4.280 ;
        RECT 431.150 4.000 431.690 4.280 ;
        RECT 432.530 4.000 433.070 4.280 ;
        RECT 433.910 4.000 433.990 4.280 ;
        RECT 434.830 4.000 435.370 4.280 ;
        RECT 436.210 4.000 436.750 4.280 ;
        RECT 437.590 4.000 437.670 4.280 ;
        RECT 438.510 4.000 439.050 4.280 ;
        RECT 439.890 4.000 440.430 4.280 ;
        RECT 441.270 4.000 441.350 4.280 ;
        RECT 442.190 4.000 442.730 4.280 ;
        RECT 443.570 4.000 444.110 4.280 ;
        RECT 444.950 4.000 445.030 4.280 ;
        RECT 445.870 4.000 446.410 4.280 ;
        RECT 447.250 4.000 447.790 4.280 ;
        RECT 448.630 4.000 448.710 4.280 ;
        RECT 449.550 4.000 450.090 4.280 ;
        RECT 450.930 4.000 451.010 4.280 ;
        RECT 451.850 4.000 452.390 4.280 ;
        RECT 453.230 4.000 453.770 4.280 ;
        RECT 454.610 4.000 454.690 4.280 ;
        RECT 455.530 4.000 456.070 4.280 ;
        RECT 456.910 4.000 457.450 4.280 ;
        RECT 458.290 4.000 458.370 4.280 ;
        RECT 459.210 4.000 459.750 4.280 ;
        RECT 460.590 4.000 461.130 4.280 ;
        RECT 461.970 4.000 462.050 4.280 ;
        RECT 462.890 4.000 463.430 4.280 ;
        RECT 464.270 4.000 464.810 4.280 ;
        RECT 465.650 4.000 465.730 4.280 ;
        RECT 466.570 4.000 467.110 4.280 ;
        RECT 467.950 4.000 468.490 4.280 ;
        RECT 469.330 4.000 469.410 4.280 ;
        RECT 470.250 4.000 470.790 4.280 ;
        RECT 471.630 4.000 472.170 4.280 ;
        RECT 473.010 4.000 473.090 4.280 ;
        RECT 473.930 4.000 474.470 4.280 ;
        RECT 475.310 4.000 475.850 4.280 ;
        RECT 476.690 4.000 476.770 4.280 ;
        RECT 477.610 4.000 478.150 4.280 ;
        RECT 478.990 4.000 479.530 4.280 ;
        RECT 480.370 4.000 480.450 4.280 ;
        RECT 481.290 4.000 481.830 4.280 ;
        RECT 482.670 4.000 483.210 4.280 ;
        RECT 484.050 4.000 484.130 4.280 ;
        RECT 484.970 4.000 485.510 4.280 ;
        RECT 486.350 4.000 486.890 4.280 ;
        RECT 487.730 4.000 487.810 4.280 ;
        RECT 488.650 4.000 489.190 4.280 ;
        RECT 490.030 4.000 490.570 4.280 ;
        RECT 491.410 4.000 491.490 4.280 ;
        RECT 492.330 4.000 492.870 4.280 ;
        RECT 493.710 4.000 494.250 4.280 ;
        RECT 495.090 4.000 495.170 4.280 ;
        RECT 496.010 4.000 496.550 4.280 ;
        RECT 497.390 4.000 497.930 4.280 ;
        RECT 498.770 4.000 498.850 4.280 ;
        RECT 499.690 4.000 500.230 4.280 ;
        RECT 501.070 4.000 501.610 4.280 ;
        RECT 502.450 4.000 502.530 4.280 ;
        RECT 503.370 4.000 503.910 4.280 ;
        RECT 504.750 4.000 505.290 4.280 ;
        RECT 506.130 4.000 506.210 4.280 ;
        RECT 507.050 4.000 507.590 4.280 ;
        RECT 508.430 4.000 508.970 4.280 ;
        RECT 509.810 4.000 509.890 4.280 ;
        RECT 510.730 4.000 511.270 4.280 ;
        RECT 512.110 4.000 512.650 4.280 ;
        RECT 513.490 4.000 513.570 4.280 ;
        RECT 514.410 4.000 514.950 4.280 ;
        RECT 515.790 4.000 516.330 4.280 ;
        RECT 517.170 4.000 517.250 4.280 ;
        RECT 518.090 4.000 518.630 4.280 ;
        RECT 519.470 4.000 520.010 4.280 ;
        RECT 520.850 4.000 520.930 4.280 ;
        RECT 521.770 4.000 522.310 4.280 ;
        RECT 523.150 4.000 523.690 4.280 ;
        RECT 524.530 4.000 524.610 4.280 ;
        RECT 525.450 4.000 525.990 4.280 ;
        RECT 526.830 4.000 526.910 4.280 ;
        RECT 527.750 4.000 528.290 4.280 ;
        RECT 529.130 4.000 529.670 4.280 ;
        RECT 530.510 4.000 530.590 4.280 ;
        RECT 531.430 4.000 531.970 4.280 ;
        RECT 532.810 4.000 533.350 4.280 ;
        RECT 534.190 4.000 534.270 4.280 ;
        RECT 535.110 4.000 535.650 4.280 ;
        RECT 536.490 4.000 537.030 4.280 ;
        RECT 537.870 4.000 537.950 4.280 ;
        RECT 538.790 4.000 539.330 4.280 ;
        RECT 540.170 4.000 540.710 4.280 ;
        RECT 541.550 4.000 541.630 4.280 ;
        RECT 542.470 4.000 543.010 4.280 ;
        RECT 543.850 4.000 544.390 4.280 ;
        RECT 545.230 4.000 545.310 4.280 ;
        RECT 546.150 4.000 546.690 4.280 ;
        RECT 547.530 4.000 548.070 4.280 ;
        RECT 548.910 4.000 548.990 4.280 ;
        RECT 549.830 4.000 550.370 4.280 ;
        RECT 551.210 4.000 551.750 4.280 ;
        RECT 552.590 4.000 552.670 4.280 ;
        RECT 553.510 4.000 554.050 4.280 ;
        RECT 554.890 4.000 555.430 4.280 ;
        RECT 556.270 4.000 556.350 4.280 ;
        RECT 557.190 4.000 557.730 4.280 ;
        RECT 558.570 4.000 559.110 4.280 ;
        RECT 559.950 4.000 560.030 4.280 ;
        RECT 560.870 4.000 561.410 4.280 ;
        RECT 562.250 4.000 562.790 4.280 ;
        RECT 563.630 4.000 563.710 4.280 ;
        RECT 564.550 4.000 565.090 4.280 ;
        RECT 565.930 4.000 566.470 4.280 ;
        RECT 567.310 4.000 567.390 4.280 ;
        RECT 568.230 4.000 568.770 4.280 ;
        RECT 569.610 4.000 570.150 4.280 ;
        RECT 570.990 4.000 571.070 4.280 ;
        RECT 571.910 4.000 572.450 4.280 ;
        RECT 573.290 4.000 573.830 4.280 ;
        RECT 574.670 4.000 574.750 4.280 ;
        RECT 575.590 4.000 576.130 4.280 ;
        RECT 576.970 4.000 577.510 4.280 ;
        RECT 578.350 4.000 578.430 4.280 ;
        RECT 579.270 4.000 579.810 4.280 ;
        RECT 580.650 4.000 581.190 4.280 ;
        RECT 582.030 4.000 582.110 4.280 ;
        RECT 582.950 4.000 583.490 4.280 ;
        RECT 584.330 4.000 584.870 4.280 ;
        RECT 585.710 4.000 585.790 4.280 ;
        RECT 586.630 4.000 587.170 4.280 ;
        RECT 588.010 4.000 588.550 4.280 ;
        RECT 589.390 4.000 589.470 4.280 ;
        RECT 590.310 4.000 590.850 4.280 ;
        RECT 591.690 4.000 592.230 4.280 ;
        RECT 593.070 4.000 593.150 4.280 ;
        RECT 593.990 4.000 594.530 4.280 ;
        RECT 595.370 4.000 595.910 4.280 ;
        RECT 596.750 4.000 596.830 4.280 ;
      LAYER met3 ;
        RECT 0.005 4.255 559.720 587.685 ;
      LAYER met4 ;
        RECT 61.415 10.240 96.920 587.760 ;
        RECT 99.320 10.240 559.720 587.760 ;
        RECT 61.415 4.255 559.720 10.240 ;
  END
END user_proj_example
END LIBRARY

